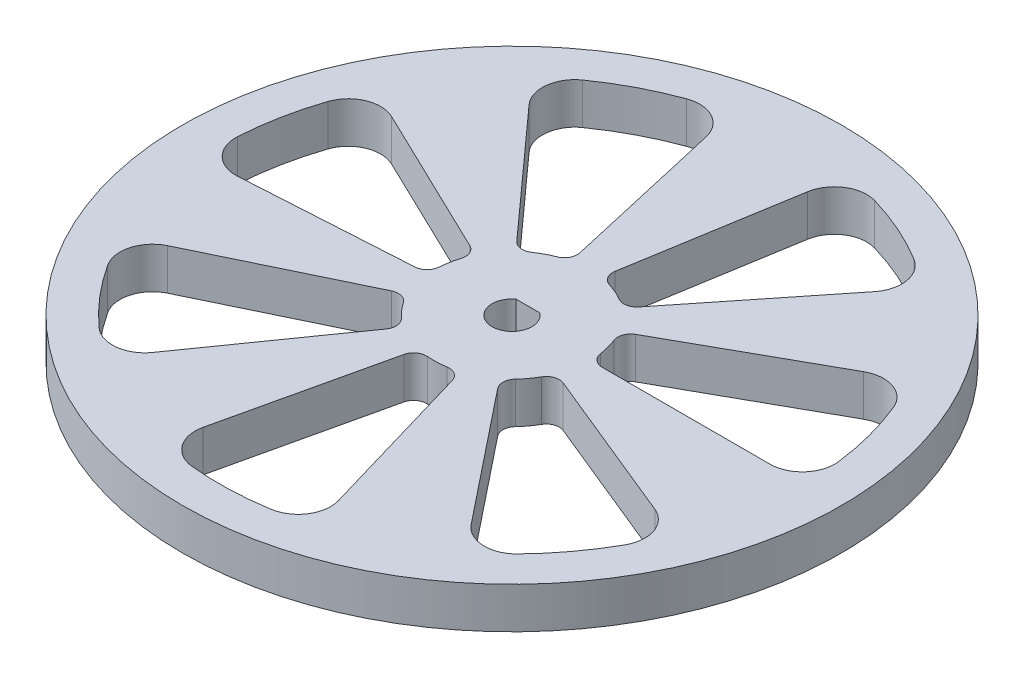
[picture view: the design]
ISO-10303-21;
HEADER;
FILE_DESCRIPTION(('STEP AP214'),'2;1');
FILE_NAME('part.step','',(''),(''),'','','');
FILE_SCHEMA(('AUTOMOTIVE_DESIGN { 1 0 10303 214 1 1 1 1 }'));
ENDSEC;
DATA;
#1=APPLICATION_CONTEXT('core data for automotive mechanical design processes');
#2=APPLICATION_PROTOCOL_DEFINITION('international standard','automotive_design',2000,#1);
#3=PRODUCT_CONTEXT('',#1,'mechanical');
#4=PRODUCT('Part','Part','',(#3));
#5=PRODUCT_RELATED_PRODUCT_CATEGORY('part','',(#4));
#6=PRODUCT_DEFINITION_FORMATION('','',#4);
#7=PRODUCT_DEFINITION_CONTEXT('part definition',#1,'design');
#8=PRODUCT_DEFINITION('design','',#6,#7);
#9=PRODUCT_DEFINITION_SHAPE('','',#8);
#10=(LENGTH_UNIT() NAMED_UNIT(*) SI_UNIT(.MILLI.,.METRE.));
#11=(NAMED_UNIT(*) PLANE_ANGLE_UNIT() SI_UNIT($,.RADIAN.));
#12=(NAMED_UNIT(*) SI_UNIT($,.STERADIAN.) SOLID_ANGLE_UNIT());
#13=UNCERTAINTY_MEASURE_WITH_UNIT(LENGTH_MEASURE(1.E-05),#10,'distance_accuracy_value','');
#14=(GEOMETRIC_REPRESENTATION_CONTEXT(3) GLOBAL_UNCERTAINTY_ASSIGNED_CONTEXT((#13)) GLOBAL_UNIT_ASSIGNED_CONTEXT((#10,
#11,#12)) REPRESENTATION_CONTEXT('',''));
#15=CARTESIAN_POINT('',(0.,0.,0.));
#16=DIRECTION('',(0.,0.,1.));
#17=DIRECTION('',(1.,0.,0.));
#18=AXIS2_PLACEMENT_3D('',#15,#16,#17);
#19=CARTESIAN_POINT('',(0.,6.35,0.));
#20=DIRECTION('',(0.,1.,0.));
#21=DIRECTION('',(0.,0.,1.));
#22=AXIS2_PLACEMENT_3D('',#19,#20,#21);
#23=PLANE('',#22);
#24=CARTESIAN_POINT('',(0.,6.35,0.));
#25=DIRECTION('',(0.,1.,0.));
#26=DIRECTION('',(0.,0.,1.));
#27=AXIS2_PLACEMENT_3D('',#24,#25,#26);
#28=CIRCLE('',#27,45.0699999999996);
#29=CARTESIAN_POINT('',(-15.4335390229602,6.35,-42.3451387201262));
#30=VERTEX_POINT('',#29);
#31=CARTESIAN_POINT('',(-25.9488114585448,6.35,-36.850564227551));
#32=VERTEX_POINT('',#31);
#33=EDGE_CURVE('E463',#30,#32,#28,.T.);
#34=ORIENTED_EDGE('',*,*,#33,.F.);
#35=CARTESIAN_POINT('',(-13.7213647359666,6.35,-37.6474308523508));
#36=DIRECTION('',(0.,1.,0.));
#37=DIRECTION('',(0.,0.,1.));
#38=AXIS2_PLACEMENT_3D('',#35,#36,#37);
#39=CIRCLE('',#38,5.);
#40=CARTESIAN_POINT('',(-8.84672517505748,6.35,-38.7600355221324));
#41=VERTEX_POINT('',#40);
#42=EDGE_CURVE('E461',#41,#30,#39,.T.);
#43=ORIENTED_EDGE('',*,*,#42,.F.);
#44=DIRECTION('',(-0.222520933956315,0.,-0.974927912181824));
#45=VECTOR('',#44,1.);
#46=CARTESIAN_POINT('',(-3.09907757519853,6.35,-13.5779460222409));
#47=LINE('',#46,#45);
#48=CARTESIAN_POINT('',(-3.09907757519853,6.35,-13.5779460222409));
#49=VERTEX_POINT('',#48);
#50=EDGE_CURVE('E477',#49,#41,#47,.T.);
#51=ORIENTED_EDGE('',*,*,#50,.F.);
#52=CARTESIAN_POINT('',(-5.04893339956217,6.35,-13.1329041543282));
#53=DIRECTION('',(0.,1.,0.));
#54=DIRECTION('',(0.,0.,1.));
#55=AXIS2_PLACEMENT_3D('',#52,#53,#54);
#56=CIRCLE('',#55,2.);
#57=CARTESIAN_POINT('',(-4.33124563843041,6.35,-11.2661089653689));
#58=VERTEX_POINT('',#57);
#59=EDGE_CURVE('E474',#58,#49,#56,.T.);
#60=ORIENTED_EDGE('',*,*,#59,.F.);
#61=CARTESIAN_POINT('',(0.,6.35,0.));
#62=DIRECTION('',(0.,-1.,0.));
#63=DIRECTION('',(0.,0.,1.));
#64=AXIS2_PLACEMENT_3D('',#61,#62,#63);
#65=CIRCLE('',#64,12.0699999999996);
#66=CARTESIAN_POINT('',(-6.86861851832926,6.35,-9.92506824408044));
#67=VERTEX_POINT('',#66);
#68=EDGE_CURVE('E472',#67,#58,#65,.T.);
#69=ORIENTED_EDGE('',*,*,#68,.F.);
#70=CARTESIAN_POINT('',(-8.00674917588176,6.35,-11.569652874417));
#71=DIRECTION('',(0.,1.,0.));
#72=DIRECTION('',(0.,0.,-1.));
#73=AXIS2_PLACEMENT_3D('',#70,#71,#72);
#74=CIRCLE('',#73,2.);
#75=CARTESIAN_POINT('',(-9.49233831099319,6.35,-10.2306140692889));
#76=VERTEX_POINT('',#75);
#77=EDGE_CURVE('E470',#76,#67,#74,.T.);
#78=ORIENTED_EDGE('',*,*,#77,.F.);
#79=DIRECTION('',(0.669519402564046,0.,0.742794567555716));
#80=VECTOR('',#79,1.);
#81=CARTESIAN_POINT('',(-9.49233831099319,6.35,-10.2306140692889));
#82=LINE('',#81,#80);
#83=CARTESIAN_POINT('',(-26.7840610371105,6.35,-29.4148194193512));
#84=VERTEX_POINT('',#83);
#85=EDGE_CURVE('E468',#84,#76,#82,.T.);
#86=ORIENTED_EDGE('',*,*,#85,.F.);
#87=CARTESIAN_POINT('',(-23.0700881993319,6.35,-32.7624164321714));
#88=DIRECTION('',(0.,1.,0.));
#89=DIRECTION('',(0.,0.,-1.));
#90=AXIS2_PLACEMENT_3D('',#87,#88,#89);
#91=CIRCLE('',#90,5.);
#92=EDGE_CURVE('E466',#32,#84,#91,.T.);
#93=ORIENTED_EDGE('',*,*,#92,.F.);
#94=EDGE_LOOP('',(#34,#43,#51,#60,#69,#78,#86,#93));
#95=FACE_BOUND('',#94,.T.);
#96=CARTESIAN_POINT('',(0.,6.35,0.));
#97=DIRECTION('',(0.,1.,0.));
#98=DIRECTION('',(0.,0.,1.));
#99=AXIS2_PLACEMENT_3D('',#96,#97,#98);
#100=CIRCLE('',#99,45.0700000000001);
#101=CARTESIAN_POINT('',(-37.8491721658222,6.35,24.469267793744));
#102=VERTEX_POINT('',#101);
#103=CARTESIAN_POINT('',(-30.152489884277,6.35,33.4982425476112));
#104=VERTEX_POINT('',#103);
#105=EDGE_CURVE('E581',#102,#104,#100,.T.);
#106=ORIENTED_EDGE('',*,*,#105,.F.);
#107=CARTESIAN_POINT('',(-33.6502402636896,6.35,21.7546829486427));
#108=DIRECTION('',(0.,1.,0.));
#109=DIRECTION('',(0.,0.,1.));
#110=AXIS2_PLACEMENT_3D('',#107,#108,#109);
#111=CIRCLE('',#110,5.);
#112=CARTESIAN_POINT('',(-35.8196589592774,6.35,17.2498386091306));
#113=VERTEX_POINT('',#112);
#114=EDGE_CURVE('E579',#113,#102,#111,.T.);
#115=ORIENTED_EDGE('',*,*,#114,.F.);
#116=DIRECTION('',(-0.900968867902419,0.,0.433883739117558));
#117=VECTOR('',#116,1.);
#118=CARTESIAN_POINT('',(-12.5479089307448,6.35,6.04275446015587));
#119=LINE('',#118,#117);
#120=CARTESIAN_POINT('',(-12.5479089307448,6.35,6.04275446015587));
#121=VERTEX_POINT('',#120);
#122=EDGE_CURVE('E595',#121,#113,#119,.T.);
#123=ORIENTED_EDGE('',*,*,#122,.F.);
#124=CARTESIAN_POINT('',(-11.6801414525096,6.35,7.84469219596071));
#125=DIRECTION('',(0.,1.,0.));
#126=DIRECTION('',(0.,0.,1.));
#127=AXIS2_PLACEMENT_3D('',#124,#125,#126);
#128=CIRCLE('',#127,2.);
#129=CARTESIAN_POINT('',(-10.0198512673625,6.35,6.72959735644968));
#130=VERTEX_POINT('',#129);
#131=EDGE_CURVE('E592',#130,#121,#128,.T.);
#132=ORIENTED_EDGE('',*,*,#131,.F.);
#133=CARTESIAN_POINT('',(0.,6.35,0.));
#134=DIRECTION('',(0.,-1.,0.));
#135=DIRECTION('',(0.,0.,1.));
#136=AXIS2_PLACEMENT_3D('',#133,#134,#135);
#137=CIRCLE('',#136,12.0700000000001);
#138=CARTESIAN_POINT('',(-8.14781465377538,6.35,8.90494336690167));
#139=VERTEX_POINT('',#138);
#140=EDGE_CURVE('E590',#139,#130,#137,.T.);
#141=ORIENTED_EDGE('',*,*,#140,.F.);
#142=CARTESIAN_POINT('',(-9.49790821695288,6.35,10.3804932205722));
#143=DIRECTION('',(0.,1.,0.));
#144=DIRECTION('',(0.,0.,-1.));
#145=AXIS2_PLACEMENT_3D('',#142,#143,#144);
#146=CIRCLE('',#145,2.);
#147=CARTESIAN_POINT('',(-7.86186722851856,6.35,11.5308713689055));
#148=VERTEX_POINT('',#147);
#149=EDGE_CURVE('E588',#148,#139,#146,.T.);
#150=ORIENTED_EDGE('',*,*,#149,.F.);
#151=DIRECTION('',(0.57518907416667,0.,-0.818020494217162));
#152=VECTOR('',#151,1.);
#153=CARTESIAN_POINT('',(-7.86186722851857,6.35,11.5308713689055));
#154=LINE('',#153,#152);
#155=CARTESIAN_POINT('',(-22.7173142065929,6.35,32.6579417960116));
#156=VERTEX_POINT('',#155);
#157=EDGE_CURVE('E586',#156,#148,#154,.T.);
#158=ORIENTED_EDGE('',*,*,#157,.F.);
#159=CARTESIAN_POINT('',(-26.8074166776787,6.35,29.7819964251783));
#160=DIRECTION('',(0.,1.,0.));
#161=DIRECTION('',(0.,0.,-1.));
#162=AXIS2_PLACEMENT_3D('',#159,#160,#161);
#163=CIRCLE('',#162,5.);
#164=EDGE_CURVE('E584',#104,#156,#163,.T.);
#165=ORIENTED_EDGE('',*,*,#164,.F.);
#166=EDGE_LOOP('',(#106,#115,#123,#132,#141,#150,#158,#165));
#167=FACE_BOUND('',#166,.T.);
#168=CARTESIAN_POINT('',(0.,6.35,0.));
#169=DIRECTION('',(0.,1.,0.));
#170=DIRECTION('',(0.,0.,1.));
#171=AXIS2_PLACEMENT_3D('',#168,#169,#170);
#172=CIRCLE('',#171,45.0700000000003);
#173=CARTESIAN_POINT('',(32.2780053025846,6.35,31.4552900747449));
#174=VERTEX_POINT('',#173);
#175=CARTESIAN_POINT('',(39.3679318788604,6.35,21.9424437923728));
#176=VERTEX_POINT('',#175);
#177=EDGE_CURVE('E699',#174,#176,#172,.T.);
#178=ORIENTED_EDGE('',*,*,#177,.F.);
#179=CARTESIAN_POINT('',(28.6971305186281,6.35,27.9656861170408));
#180=DIRECTION('',(0.,1.,0.));
#181=DIRECTION('',(0.,0.,1.));
#182=AXIS2_PLACEMENT_3D('',#179,#180,#181);
#183=CIRCLE('',#182,5.);
#184=CARTESIAN_POINT('',(24.7879731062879,6.35,31.0831351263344));
#185=VERTEX_POINT('',#184);
#186=EDGE_CURVE('E697',#185,#174,#183,.T.);
#187=ORIENTED_EDGE('',*,*,#186,.F.);
#188=DIRECTION('',(0.623489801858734,0.,0.78183148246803));
#189=VECTOR('',#188,1.);
#190=CARTESIAN_POINT('',(8.68342240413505,6.35,10.8886672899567));
#191=LINE('',#190,#189);
#192=CARTESIAN_POINT('',(8.68342240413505,6.35,10.8886672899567));
#193=VERTEX_POINT('',#192);
#194=EDGE_CURVE('E713',#193,#185,#191,.T.);
#195=ORIENTED_EDGE('',*,*,#194,.F.);
#196=CARTESIAN_POINT('',(10.2470853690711,6.35,9.6416876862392));
#197=DIRECTION('',(0.,1.,0.));
#198=DIRECTION('',(0.,0.,1.));
#199=AXIS2_PLACEMENT_3D('',#196,#197,#198);
#200=CIRCLE('',#199,2.);
#201=CARTESIAN_POINT('',(8.79049896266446,6.35,8.2711563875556));
#202=VERTEX_POINT('',#201);
#203=EDGE_CURVE('E710',#202,#193,#200,.T.);
#204=ORIENTED_EDGE('',*,*,#203,.F.);
#205=CARTESIAN_POINT('',(0.,6.35,0.));
#206=DIRECTION('',(0.,-1.,0.));
#207=DIRECTION('',(0.,0.,1.));
#208=AXIS2_PLACEMENT_3D('',#205,#206,#207);
#209=CIRCLE('',#208,12.0700000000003);
#210=CARTESIAN_POINT('',(10.4947371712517,6.35,5.96199561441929));
#211=VERTEX_POINT('',#210);
#212=EDGE_CURVE('E708',#211,#202,#209,.T.);
#213=ORIENTED_EDGE('',*,*,#212,.F.);
#214=CARTESIAN_POINT('',(12.2337159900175,6.35,6.94989878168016));
#215=DIRECTION('',(0.,1.,0.));
#216=DIRECTION('',(0.,0.,-1.));
#217=AXIS2_PLACEMENT_3D('',#214,#215,#216);
#218=CIRCLE('',#217,2.);
#219=CARTESIAN_POINT('',(12.9911983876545,6.35,5.09889353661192));
#220=VERTEX_POINT('',#219);
#221=EDGE_CURVE('E706',#220,#211,#218,.T.);
#222=ORIENTED_EDGE('',*,*,#221,.F.);
#223=DIRECTION('',(-0.925502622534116,0.,-0.378741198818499));
#224=VECTOR('',#223,1.);
#225=CARTESIAN_POINT('',(12.9911983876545,6.35,5.09889353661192));
#226=LINE('',#225,#224);
#227=CARTESIAN_POINT('',(36.894216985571,6.35,14.8806680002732));
#228=VERTEX_POINT('',#227);
#229=EDGE_CURVE('E704',#228,#220,#226,.T.);
#230=ORIENTED_EDGE('',*,*,#229,.F.);
#231=CARTESIAN_POINT('',(35.0005109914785,6.35,19.5081811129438));
#232=DIRECTION('',(0.,1.,0.));
#233=DIRECTION('',(0.,0.,-1.));
#234=AXIS2_PLACEMENT_3D('',#231,#232,#233);
#235=CIRCLE('',#234,5.);
#236=EDGE_CURVE('E702',#176,#228,#235,.T.);
#237=ORIENTED_EDGE('',*,*,#236,.F.);
#238=EDGE_LOOP('',(#178,#187,#195,#204,#213,#222,#230,#237));
#239=FACE_BOUND('',#238,.T.);
#240=CARTESIAN_POINT('',(0.,6.35,0.));
#241=DIRECTION('',(0.,1.,0.));
#242=DIRECTION('',(0.,0.,1.));
#243=AXIS2_PLACEMENT_3D('',#240,#241,#242);
#244=CIRCLE('',#243,45.07);
#245=CARTESIAN_POINT('',(44.7177432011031,6.35,-5.62390816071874));
#246=VERTEX_POINT('',#245);
#247=CARTESIAN_POINT('',(41.7007974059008,6.35,-17.0981986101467));
#248=VERTEX_POINT('',#247);
#249=EDGE_CURVE('E775',#246,#248,#244,.T.);
#250=ORIENTED_EDGE('',*,*,#249,.F.);
#251=CARTESIAN_POINT('',(39.756822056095,6.35,-5.));
#252=DIRECTION('',(0.,1.,0.));
#253=DIRECTION('',(0.,0.,1.));
#254=AXIS2_PLACEMENT_3D('',#251,#252,#253);
#255=CIRCLE('',#254,5.);
#256=CARTESIAN_POINT('',(39.756822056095,6.35,0.));
#257=VERTEX_POINT('',#256);
#258=EDGE_CURVE('E773',#257,#246,#255,.T.);
#259=ORIENTED_EDGE('',*,*,#258,.F.);
#260=DIRECTION('',(1.,0.,0.));
#261=VECTOR('',#260,1.);
#262=CARTESIAN_POINT('',(13.9271282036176,6.35,0.));
#263=LINE('',#262,#261);
#264=CARTESIAN_POINT('',(13.9271282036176,6.35,0.));
#265=VERTEX_POINT('',#264);
#266=EDGE_CURVE('E789',#265,#257,#263,.T.);
#267=ORIENTED_EDGE('',*,*,#266,.F.);
#268=CARTESIAN_POINT('',(13.9271282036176,6.35,-2.));
#269=DIRECTION('',(0.,1.,0.));
#270=DIRECTION('',(0.,0.,1.));
#271=AXIS2_PLACEMENT_3D('',#268,#269,#270);
#272=CIRCLE('',#271,2.);
#273=CARTESIAN_POINT('',(11.9474369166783,6.35,-1.71570717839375));
#274=VERTEX_POINT('',#273);
#275=EDGE_CURVE('E786',#274,#265,#272,.T.);
#276=ORIENTED_EDGE('',*,*,#275,.F.);
#277=CARTESIAN_POINT('',(0.,6.35,0.));
#278=DIRECTION('',(0.,-1.,0.));
#279=DIRECTION('',(0.,0.,1.));
#280=AXIS2_PLACEMENT_3D('',#277,#278,#279);
#281=CIRCLE('',#280,12.07);
#282=CARTESIAN_POINT('',(11.2046374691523,6.35,-4.4878724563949));
#283=VERTEX_POINT('',#282);
#284=EDGE_CURVE('E784',#283,#274,#281,.T.);
#285=ORIENTED_EDGE('',*,*,#284,.F.);
#286=CARTESIAN_POINT('',(13.0612468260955,6.35,-5.23151329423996));
#287=DIRECTION('',(0.,1.,0.));
#288=DIRECTION('',(0.,0.,-1.));
#289=AXIS2_PLACEMENT_3D('',#286,#287,#288);
#290=CIRCLE('',#289,2.);
#291=CARTESIAN_POINT('',(12.0863552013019,6.35,-6.977819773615));
#292=VERTEX_POINT('',#291);
#293=EDGE_CURVE('E782',#292,#283,#290,.T.);
#294=ORIENTED_EDGE('',*,*,#293,.F.);
#295=DIRECTION('',(-0.87315323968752,0.,0.487445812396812));
#296=VECTOR('',#295,1.);
#297=CARTESIAN_POINT('',(12.0863552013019,6.35,-6.977819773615));
#298=LINE('',#297,#296);
#299=CARTESIAN_POINT('',(34.6373427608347,6.35,-19.56711561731));
#300=VERTEX_POINT('',#299);
#301=EDGE_CURVE('E780',#300,#292,#298,.T.);
#302=ORIENTED_EDGE('',*,*,#301,.F.);
#303=CARTESIAN_POINT('',(37.0745718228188,6.35,-15.2013494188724));
#304=DIRECTION('',(0.,1.,0.));
#305=DIRECTION('',(0.,0.,-1.));
#306=AXIS2_PLACEMENT_3D('',#303,#304,#305);
#307=CIRCLE('',#306,5.);
#308=EDGE_CURVE('E778',#248,#300,#307,.T.);
#309=ORIENTED_EDGE('',*,*,#308,.F.);
#310=EDGE_LOOP('',(#250,#259,#267,#276,#285,#294,#302,#309));
#311=FACE_BOUND('',#310,.T.);
#312=CARTESIAN_POINT('',(0.,6.35,0.));
#313=DIRECTION('',(0.,1.,0.));
#314=DIRECTION('',(0.,0.,1.));
#315=AXIS2_PLACEMENT_3D('',#312,#313,#314);
#316=CIRCLE('',#315,50.8);
#317=CARTESIAN_POINT('',(0.,6.35,50.8));
#318=VERTEX_POINT('',#317);
#319=EDGE_CURVE('E11',#318,#318,#316,.T.);
#320=ORIENTED_EDGE('',*,*,#319,.T.);
#321=EDGE_LOOP('',(#320));
#322=FACE_BOUND('',#321,.T.);
#323=DIRECTION('',(-1.,0.,0.));
#324=VECTOR('',#323,1.);
#325=CARTESIAN_POINT('',(1.83187666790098,6.35,-2.46356));
#326=LINE('',#325,#324);
#327=CARTESIAN_POINT('',(1.83187666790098,6.35,-2.46356));
#328=VERTEX_POINT('',#327);
#329=CARTESIAN_POINT('',(-1.83187666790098,6.35,-2.46356));
#330=VERTEX_POINT('',#329);
#331=EDGE_CURVE('E759',#328,#330,#326,.T.);
#332=ORIENTED_EDGE('',*,*,#331,.F.);
#333=CARTESIAN_POINT('',(0.,6.35,0.));
#334=DIRECTION('',(0.,1.,0.));
#335=DIRECTION('',(0.,0.,1.));
#336=AXIS2_PLACEMENT_3D('',#333,#334,#335);
#337=CIRCLE('',#336,3.07);
#338=EDGE_CURVE('E756',#330,#328,#337,.T.);
#339=ORIENTED_EDGE('',*,*,#338,.F.);
#340=EDGE_LOOP('',(#332,#339));
#341=FACE_BOUND('',#340,.T.);
#342=CARTESIAN_POINT('',(0.,6.35,0.));
#343=DIRECTION('',(0.,1.,0.));
#344=DIRECTION('',(0.,0.,1.));
#345=AXIS2_PLACEMENT_3D('',#342,#343,#344);
#346=CIRCLE('',#345,45.0700000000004);
#347=CARTESIAN_POINT('',(-4.46772894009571,6.35,44.8480133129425));
#348=VERTEX_POINT('',#347);
#349=CARTESIAN_POINT('',(7.39021068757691,6.35,44.4599784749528));
#350=VERTEX_POINT('',#349);
#351=EDGE_CURVE('E640',#348,#350,#346,.T.);
#352=ORIENTED_EDGE('',*,*,#351,.F.);
#353=CARTESIAN_POINT('',(-3.9720856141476,6.35,39.8726401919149));
#354=DIRECTION('',(0.,1.,0.));
#355=DIRECTION('',(0.,0.,1.));
#356=AXIS2_PLACEMENT_3D('',#353,#354,#355);
#357=CIRCLE('',#356,5.);
#358=CARTESIAN_POINT('',(-8.84672517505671,6.35,38.7600355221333));
#359=VERTEX_POINT('',#358);
#360=EDGE_CURVE('E638',#359,#348,#357,.T.);
#361=ORIENTED_EDGE('',*,*,#360,.F.);
#362=DIRECTION('',(-0.222520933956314,0.,0.974927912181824));
#363=VECTOR('',#362,1.);
#364=CARTESIAN_POINT('',(-3.09907757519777,6.35,13.5779460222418));
#365=LINE('',#364,#363);
#366=CARTESIAN_POINT('',(-3.09907757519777,6.35,13.5779460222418));
#367=VERTEX_POINT('',#366);
#368=EDGE_CURVE('E654',#367,#359,#365,.T.);
#369=ORIENTED_EDGE('',*,*,#368,.F.);
#370=CARTESIAN_POINT('',(-1.14922175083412,6.35,14.0229878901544));
#371=DIRECTION('',(0.,1.,0.));
#372=DIRECTION('',(0.,0.,1.));
#373=AXIS2_PLACEMENT_3D('',#370,#371,#372);
#374=CIRCLE('',#373,2.);
#375=CARTESIAN_POINT('',(-0.98586400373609,6.35,12.0296704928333));
#376=VERTEX_POINT('',#375);
#377=EDGE_CURVE('E651',#376,#367,#374,.T.);
#378=ORIENTED_EDGE('',*,*,#377,.F.);
#379=CARTESIAN_POINT('',(0.,6.35,0.));
#380=DIRECTION('',(0.,-1.,0.));
#381=DIRECTION('',(0.,0.,1.));
#382=AXIS2_PLACEMENT_3D('',#379,#380,#381);
#383=CIRCLE('',#382,12.0700000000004);
#384=CARTESIAN_POINT('',(1.88208572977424,6.35,11.922359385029));
#385=VERTEX_POINT('',#384);
#386=EDGE_CURVE('E649',#385,#376,#383,.T.);
#387=ORIENTED_EDGE('',*,*,#386,.F.);
#388=CARTESIAN_POINT('',(2.19394749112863,6.35,13.8978953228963));
#389=DIRECTION('',(0.,1.,0.));
#390=DIRECTION('',(0.,0.,-1.));
#391=AXIS2_PLACEMENT_3D('',#388,#389,#390);
#392=CIRCLE('',#391,2.);
#393=CARTESIAN_POINT('',(4.1134042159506,6.35,13.3360360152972));
#394=VERTEX_POINT('',#393);
#395=EDGE_CURVE('E647',#394,#385,#392,.T.);
#396=ORIENTED_EDGE('',*,*,#395,.F.);
#397=DIRECTION('',(-0.280929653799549,0.,-0.959728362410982));
#398=VECTOR('',#397,1.);
#399=CARTESIAN_POINT('',(4.11340421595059,6.35,13.3360360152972));
#400=LINE('',#399,#398);
#401=CARTESIAN_POINT('',(11.368993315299,6.35,38.1230051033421));
#402=VERTEX_POINT('',#401);
#403=EDGE_CURVE('E645',#402,#394,#400,.T.);
#404=ORIENTED_EDGE('',*,*,#403,.F.);
#405=CARTESIAN_POINT('',(6.57035150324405,6.35,39.5276533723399));
#406=DIRECTION('',(0.,1.,0.));
#407=DIRECTION('',(0.,0.,-1.));
#408=AXIS2_PLACEMENT_3D('',#405,#406,#407);
#409=CIRCLE('',#408,5.);
#410=EDGE_CURVE('E643',#350,#402,#409,.T.);
#411=ORIENTED_EDGE('',*,*,#410,.F.);
#412=EDGE_LOOP('',(#352,#361,#369,#378,#387,#396,#404,#411));
#413=FACE_BOUND('',#412,.T.);
#414=CARTESIAN_POINT('',(0.,6.35,0.));
#415=DIRECTION('',(0.,1.,0.));
#416=DIRECTION('',(0.,0.,1.));
#417=AXIS2_PLACEMENT_3D('',#414,#415,#416);
#418=CIRCLE('',#417,45.0699999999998);
#419=CARTESIAN_POINT('',(-42.7294167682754,6.35,-14.3353354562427));
#420=VERTEX_POINT('',#419);
#421=CARTESIAN_POINT('',(-44.9897505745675,6.35,-2.68835325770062));
#422=VERTEX_POINT('',#421);
#423=EDGE_CURVE('E522',#420,#422,#418,.T.);
#424=ORIENTED_EDGE('',*,*,#423,.F.);
#425=CARTESIAN_POINT('',(-37.9890776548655,6.35,-12.744994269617));
#426=DIRECTION('',(0.,1.,0.));
#427=DIRECTION('',(0.,0.,1.));
#428=AXIS2_PLACEMENT_3D('',#425,#426,#427);
#429=CIRCLE('',#428,5.);
#430=CARTESIAN_POINT('',(-35.8196589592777,6.35,-17.2498386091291));
#431=VERTEX_POINT('',#430);
#432=EDGE_CURVE('E520',#431,#420,#429,.T.);
#433=ORIENTED_EDGE('',*,*,#432,.F.);
#434=DIRECTION('',(-0.900968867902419,0.,-0.433883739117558));
#435=VECTOR('',#434,1.);
#436=CARTESIAN_POINT('',(-12.5479089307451,6.35,-6.0427544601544));
#437=LINE('',#436,#435);
#438=CARTESIAN_POINT('',(-12.5479089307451,6.35,-6.0427544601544));
#439=VERTEX_POINT('',#438);
#440=EDGE_CURVE('E536',#439,#431,#437,.T.);
#441=ORIENTED_EDGE('',*,*,#440,.F.);
#442=CARTESIAN_POINT('',(-13.4156764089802,6.35,-4.24081672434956));
#443=DIRECTION('',(0.,1.,0.));
#444=DIRECTION('',(0.,0.,1.));
#445=AXIS2_PLACEMENT_3D('',#442,#443,#444);
#446=CIRCLE('',#445,2.);
#447=CARTESIAN_POINT('',(-11.5086861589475,6.35,-3.63799984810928));
#448=VERTEX_POINT('',#447);
#449=EDGE_CURVE('E533',#448,#439,#446,.T.);
#450=ORIENTED_EDGE('',*,*,#449,.F.);
#451=CARTESIAN_POINT('',(0.,6.35,0.));
#452=DIRECTION('',(0.,-1.,0.));
#453=DIRECTION('',(0.,0.,1.));
#454=AXIS2_PLACEMENT_3D('',#451,#452,#453);
#455=CIRCLE('',#454,12.0699999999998);
#456=CARTESIAN_POINT('',(-12.0422444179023,6.35,-0.818076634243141));
#457=VERTEX_POINT('',#456);
#458=EDGE_CURVE('E531',#457,#448,#455,.T.);
#459=ORIENTED_EDGE('',*,*,#458,.F.);
#460=CARTESIAN_POINT('',(-14.0376453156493,6.35,-0.953632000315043));
#461=DIRECTION('',(0.,1.,0.));
#462=DIRECTION('',(0.,0.,-1.));
#463=AXIS2_PLACEMENT_3D('',#460,#461,#462);
#464=CIRCLE('',#463,2.);
#465=CARTESIAN_POINT('',(-13.9169922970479,6.35,1.042725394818));
#466=VERTEX_POINT('',#465);
#467=EDGE_CURVE('E529',#466,#457,#464,.T.);
#468=ORIENTED_EDGE('',*,*,#467,.F.);
#469=DIRECTION('',(0.998178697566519,0.,-0.0603265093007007));
#470=VECTOR('',#469,1.);
#471=CARTESIAN_POINT('',(-13.9169922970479,6.35,1.04272539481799));
#472=LINE('',#471,#470);
#473=CARTESIAN_POINT('',(-39.6970207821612,6.35,2.60078221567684));
#474=VERTEX_POINT('',#473);
#475=EDGE_CURVE('E527',#474,#466,#472,.T.);
#476=ORIENTED_EDGE('',*,*,#475,.F.);
#477=CARTESIAN_POINT('',(-39.9986533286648,6.35,-2.39011127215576));
#478=DIRECTION('',(0.,1.,0.));
#479=DIRECTION('',(0.,0.,-1.));
#480=AXIS2_PLACEMENT_3D('',#477,#478,#479);
#481=CIRCLE('',#480,5.);
#482=EDGE_CURVE('E525',#422,#474,#481,.T.);
#483=ORIENTED_EDGE('',*,*,#482,.F.);
#484=EDGE_LOOP('',(#424,#433,#441,#450,#459,#468,#476,#483));
#485=FACE_BOUND('',#484,.T.);
#486=CARTESIAN_POINT('',(0.,6.35,0.));
#487=DIRECTION('',(0.,1.,0.));
#488=DIRECTION('',(0.,0.,1.));
#489=AXIS2_PLACEMENT_3D('',#486,#487,#488);
#490=CIRCLE('',#489,45.0699999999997);
#491=CARTESIAN_POINT('',(23.4841083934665,6.35,-38.4681888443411));
#492=VERTEX_POINT('',#491);
#493=CARTESIAN_POINT('',(12.6321119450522,6.35,-43.2635487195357));
#494=VERTEX_POINT('',#493);
#495=EDGE_CURVE('E404',#492,#494,#490,.T.);
#496=ORIENTED_EDGE('',*,*,#495,.F.);
#497=CARTESIAN_POINT('',(20.8788156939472,6.35,-34.2005841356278));
#498=DIRECTION('',(0.,1.,0.));
#499=DIRECTION('',(0.,0.,1.));
#500=AXIS2_PLACEMENT_3D('',#497,#498,#499);
#501=CIRCLE('',#500,5.);
#502=CARTESIAN_POINT('',(24.7879731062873,6.35,-31.0831351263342));
#503=VERTEX_POINT('',#502);
#504=EDGE_CURVE('E396',#503,#492,#501,.T.);
#505=ORIENTED_EDGE('',*,*,#504,.F.);
#506=DIRECTION('',(0.623489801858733,0.,-0.78183148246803));
#507=VECTOR('',#506,1.);
#508=CARTESIAN_POINT('',(8.68342240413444,6.35,-10.8886672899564));
#509=LINE('',#508,#507);
#510=CARTESIAN_POINT('',(8.68342240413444,6.35,-10.8886672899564));
#511=VERTEX_POINT('',#510);
#512=EDGE_CURVE('E429',#511,#503,#509,.T.);
#513=ORIENTED_EDGE('',*,*,#512,.F.);
#514=CARTESIAN_POINT('',(7.11975943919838,6.35,-12.1356468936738));
#515=DIRECTION('',(0.,1.,0.));
#516=DIRECTION('',(0.,0.,1.));
#517=AXIS2_PLACEMENT_3D('',#514,#515,#516);
#518=CIRCLE('',#517,2.);
#519=CARTESIAN_POINT('',(6.10771118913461,6.35,-10.410608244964));
#520=VERTEX_POINT('',#519);
#521=EDGE_CURVE('E427',#520,#511,#518,.T.);
#522=ORIENTED_EDGE('',*,*,#521,.F.);
#523=CARTESIAN_POINT('',(0.,6.35,0.));
#524=DIRECTION('',(0.,-1.,0.));
#525=DIRECTION('',(0.,0.,1.));
#526=AXIS2_PLACEMENT_3D('',#523,#524,#525);
#527=CIRCLE('',#526,12.0699999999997);
#528=CARTESIAN_POINT('',(3.47721721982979,6.35,-11.5582810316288));
#529=VERTEX_POINT('',#528);
#530=EDGE_CURVE('E425',#529,#520,#527,.T.);
#531=ORIENTED_EDGE('',*,*,#530,.F.);
#532=CARTESIAN_POINT('',(4.05339240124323,6.35,-13.4734891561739));
#533=DIRECTION('',(0.,1.,0.));
#534=DIRECTION('',(0.,0.,-1.));
#535=AXIS2_PLACEMENT_3D('',#532,#533,#534);
#536=CIRCLE('',#535,2.);
#537=CARTESIAN_POINT('',(2.0802400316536,6.35,-13.800092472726));
#538=VERTEX_POINT('',#537);
#539=EDGE_CURVE('E423',#538,#529,#536,.T.);
#540=ORIENTED_EDGE('',*,*,#539,.F.);
#541=DIRECTION('',(-0.16330165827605,0.,0.986576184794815));
#542=VECTOR('',#541,1.);
#543=CARTESIAN_POINT('',(2.0802400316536,6.35,-13.800092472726));
#544=LINE('',#543,#542);
#545=CARTESIAN_POINT('',(6.29784296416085,6.35,-39.28046207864));
#546=VERTEX_POINT('',#545);
#547=EDGE_CURVE('E419',#546,#538,#544,.T.);
#548=ORIENTED_EDGE('',*,*,#547,.F.);
#549=CARTESIAN_POINT('',(11.2307238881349,6.35,-38.4639537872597));
#550=DIRECTION('',(0.,1.,0.));
#551=DIRECTION('',(0.,0.,-1.));
#552=AXIS2_PLACEMENT_3D('',#549,#550,#551);
#553=CIRCLE('',#552,5.);
#554=EDGE_CURVE('E417',#494,#546,#553,.T.);
#555=ORIENTED_EDGE('',*,*,#554,.F.);
#556=EDGE_LOOP('',(#496,#505,#513,#522,#531,#540,#548,#555));
#557=FACE_BOUND('',#556,.T.);
#558=ADVANCED_FACE('F31',(#95,#167,#239,#311,#322,#341,#413,#485,#557),#23,.T.);
#559=CARTESIAN_POINT('',(0.,0.,0.));
#560=DIRECTION('',(0.,1.,0.));
#561=DIRECTION('',(0.,0.,1.));
#562=AXIS2_PLACEMENT_3D('',#559,#560,#561);
#563=PLANE('',#562);
#564=CARTESIAN_POINT('',(-13.7213647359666,0.,-37.6474308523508));
#565=DIRECTION('',(0.,1.,0.));
#566=DIRECTION('',(0.,0.,1.));
#567=AXIS2_PLACEMENT_3D('',#564,#565,#566);
#568=CIRCLE('',#567,5.);
#569=CARTESIAN_POINT('',(-8.84672517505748,0.,-38.7600355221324));
#570=VERTEX_POINT('',#569);
#571=CARTESIAN_POINT('',(-15.4335390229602,0.,-42.3451387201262));
#572=VERTEX_POINT('',#571);
#573=EDGE_CURVE('E412',#570,#572,#568,.T.);
#574=ORIENTED_EDGE('',*,*,#573,.T.);
#575=CARTESIAN_POINT('',(0.,0.,0.));
#576=DIRECTION('',(0.,1.,0.));
#577=DIRECTION('',(0.,0.,1.));
#578=AXIS2_PLACEMENT_3D('',#575,#576,#577);
#579=CIRCLE('',#578,45.0699999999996);
#580=CARTESIAN_POINT('',(-25.9488114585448,0.,-36.850564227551));
#581=VERTEX_POINT('',#580);
#582=EDGE_CURVE('E482',#572,#581,#579,.T.);
#583=ORIENTED_EDGE('',*,*,#582,.T.);
#584=CARTESIAN_POINT('',(-23.0700881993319,0.,-32.7624164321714));
#585=DIRECTION('',(0.,1.,0.));
#586=DIRECTION('',(0.,0.,-1.));
#587=AXIS2_PLACEMENT_3D('',#584,#585,#586);
#588=CIRCLE('',#587,5.);
#589=CARTESIAN_POINT('',(-26.7840610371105,0.,-29.4148194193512));
#590=VERTEX_POINT('',#589);
#591=EDGE_CURVE('E485',#581,#590,#588,.T.);
#592=ORIENTED_EDGE('',*,*,#591,.T.);
#593=DIRECTION('',(0.669519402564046,0.,0.742794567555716));
#594=VECTOR('',#593,1.);
#595=CARTESIAN_POINT('',(-9.49233831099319,0.,-10.2306140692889));
#596=LINE('',#595,#594);
#597=CARTESIAN_POINT('',(-9.49233831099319,0.,-10.2306140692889));
#598=VERTEX_POINT('',#597);
#599=EDGE_CURVE('E488',#590,#598,#596,.T.);
#600=ORIENTED_EDGE('',*,*,#599,.T.);
#601=CARTESIAN_POINT('',(-8.00674917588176,0.,-11.569652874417));
#602=DIRECTION('',(0.,1.,0.));
#603=DIRECTION('',(0.,0.,-1.));
#604=AXIS2_PLACEMENT_3D('',#601,#602,#603);
#605=CIRCLE('',#604,2.);
#606=CARTESIAN_POINT('',(-6.86861851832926,0.,-9.92506824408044));
#607=VERTEX_POINT('',#606);
#608=EDGE_CURVE('E491',#598,#607,#605,.T.);
#609=ORIENTED_EDGE('',*,*,#608,.T.);
#610=CARTESIAN_POINT('',(0.,0.,0.));
#611=DIRECTION('',(0.,-1.,0.));
#612=DIRECTION('',(0.,0.,1.));
#613=AXIS2_PLACEMENT_3D('',#610,#611,#612);
#614=CIRCLE('',#613,12.0699999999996);
#615=CARTESIAN_POINT('',(-4.33124563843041,0.,-11.2661089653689));
#616=VERTEX_POINT('',#615);
#617=EDGE_CURVE('E494',#607,#616,#614,.T.);
#618=ORIENTED_EDGE('',*,*,#617,.T.);
#619=CARTESIAN_POINT('',(-5.04893339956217,0.,-13.1329041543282));
#620=DIRECTION('',(0.,1.,0.));
#621=DIRECTION('',(0.,0.,1.));
#622=AXIS2_PLACEMENT_3D('',#619,#620,#621);
#623=CIRCLE('',#622,2.);
#624=CARTESIAN_POINT('',(-3.09907757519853,0.,-13.5779460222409));
#625=VERTEX_POINT('',#624);
#626=EDGE_CURVE('E497',#616,#625,#623,.T.);
#627=ORIENTED_EDGE('',*,*,#626,.T.);
#628=DIRECTION('',(-0.222520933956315,0.,-0.974927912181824));
#629=VECTOR('',#628,1.);
#630=CARTESIAN_POINT('',(-3.09907757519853,0.,-13.5779460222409));
#631=LINE('',#630,#629);
#632=EDGE_CURVE('E464',#625,#570,#631,.T.);
#633=ORIENTED_EDGE('',*,*,#632,.T.);
#634=EDGE_LOOP('',(#574,#583,#592,#600,#609,#618,#627,#633));
#635=FACE_BOUND('',#634,.T.);
#636=CARTESIAN_POINT('',(-33.6502402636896,0.,21.7546829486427));
#637=DIRECTION('',(0.,1.,0.));
#638=DIRECTION('',(0.,0.,1.));
#639=AXIS2_PLACEMENT_3D('',#636,#637,#638);
#640=CIRCLE('',#639,5.);
#641=CARTESIAN_POINT('',(-35.8196589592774,0.,17.2498386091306));
#642=VERTEX_POINT('',#641);
#643=CARTESIAN_POINT('',(-37.8491721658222,0.,24.469267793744));
#644=VERTEX_POINT('',#643);
#645=EDGE_CURVE('E578',#642,#644,#640,.T.);
#646=ORIENTED_EDGE('',*,*,#645,.T.);
#647=CARTESIAN_POINT('',(0.,0.,0.));
#648=DIRECTION('',(0.,1.,0.));
#649=DIRECTION('',(0.,0.,1.));
#650=AXIS2_PLACEMENT_3D('',#647,#648,#649);
#651=CIRCLE('',#650,45.0700000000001);
#652=CARTESIAN_POINT('',(-30.152489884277,0.,33.4982425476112));
#653=VERTEX_POINT('',#652);
#654=EDGE_CURVE('E600',#644,#653,#651,.T.);
#655=ORIENTED_EDGE('',*,*,#654,.T.);
#656=CARTESIAN_POINT('',(-26.8074166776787,0.,29.7819964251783));
#657=DIRECTION('',(0.,1.,0.));
#658=DIRECTION('',(0.,0.,-1.));
#659=AXIS2_PLACEMENT_3D('',#656,#657,#658);
#660=CIRCLE('',#659,5.);
#661=CARTESIAN_POINT('',(-22.7173142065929,0.,32.6579417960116));
#662=VERTEX_POINT('',#661);
#663=EDGE_CURVE('E603',#653,#662,#660,.T.);
#664=ORIENTED_EDGE('',*,*,#663,.T.);
#665=DIRECTION('',(0.57518907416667,0.,-0.818020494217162));
#666=VECTOR('',#665,1.);
#667=CARTESIAN_POINT('',(-7.86186722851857,0.,11.5308713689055));
#668=LINE('',#667,#666);
#669=CARTESIAN_POINT('',(-7.86186722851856,0.,11.5308713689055));
#670=VERTEX_POINT('',#669);
#671=EDGE_CURVE('E606',#662,#670,#668,.T.);
#672=ORIENTED_EDGE('',*,*,#671,.T.);
#673=CARTESIAN_POINT('',(-9.49790821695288,0.,10.3804932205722));
#674=DIRECTION('',(0.,1.,0.));
#675=DIRECTION('',(0.,0.,-1.));
#676=AXIS2_PLACEMENT_3D('',#673,#674,#675);
#677=CIRCLE('',#676,2.);
#678=CARTESIAN_POINT('',(-8.14781465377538,0.,8.90494336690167));
#679=VERTEX_POINT('',#678);
#680=EDGE_CURVE('E609',#670,#679,#677,.T.);
#681=ORIENTED_EDGE('',*,*,#680,.T.);
#682=CARTESIAN_POINT('',(0.,0.,0.));
#683=DIRECTION('',(0.,-1.,0.));
#684=DIRECTION('',(0.,0.,1.));
#685=AXIS2_PLACEMENT_3D('',#682,#683,#684);
#686=CIRCLE('',#685,12.0700000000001);
#687=CARTESIAN_POINT('',(-10.0198512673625,0.,6.72959735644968));
#688=VERTEX_POINT('',#687);
#689=EDGE_CURVE('E612',#679,#688,#686,.T.);
#690=ORIENTED_EDGE('',*,*,#689,.T.);
#691=CARTESIAN_POINT('',(-11.6801414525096,0.,7.84469219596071));
#692=DIRECTION('',(0.,1.,0.));
#693=DIRECTION('',(0.,0.,1.));
#694=AXIS2_PLACEMENT_3D('',#691,#692,#693);
#695=CIRCLE('',#694,2.);
#696=CARTESIAN_POINT('',(-12.5479089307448,0.,6.04275446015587));
#697=VERTEX_POINT('',#696);
#698=EDGE_CURVE('E615',#688,#697,#695,.T.);
#699=ORIENTED_EDGE('',*,*,#698,.T.);
#700=DIRECTION('',(-0.900968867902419,0.,0.433883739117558));
#701=VECTOR('',#700,1.);
#702=CARTESIAN_POINT('',(-12.5479089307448,0.,6.04275446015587));
#703=LINE('',#702,#701);
#704=EDGE_CURVE('E582',#697,#642,#703,.T.);
#705=ORIENTED_EDGE('',*,*,#704,.T.);
#706=EDGE_LOOP('',(#646,#655,#664,#672,#681,#690,#699,#705));
#707=FACE_BOUND('',#706,.T.);
#708=CARTESIAN_POINT('',(28.6971305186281,0.,27.9656861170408));
#709=DIRECTION('',(0.,1.,0.));
#710=DIRECTION('',(0.,0.,1.));
#711=AXIS2_PLACEMENT_3D('',#708,#709,#710);
#712=CIRCLE('',#711,5.);
#713=CARTESIAN_POINT('',(24.7879731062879,0.,31.0831351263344));
#714=VERTEX_POINT('',#713);
#715=CARTESIAN_POINT('',(32.2780053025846,0.,31.4552900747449));
#716=VERTEX_POINT('',#715);
#717=EDGE_CURVE('E696',#714,#716,#712,.T.);
#718=ORIENTED_EDGE('',*,*,#717,.T.);
#719=CARTESIAN_POINT('',(0.,0.,0.));
#720=DIRECTION('',(0.,1.,0.));
#721=DIRECTION('',(0.,0.,1.));
#722=AXIS2_PLACEMENT_3D('',#719,#720,#721);
#723=CIRCLE('',#722,45.0700000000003);
#724=CARTESIAN_POINT('',(39.3679318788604,0.,21.9424437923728));
#725=VERTEX_POINT('',#724);
#726=EDGE_CURVE('E718',#716,#725,#723,.T.);
#727=ORIENTED_EDGE('',*,*,#726,.T.);
#728=CARTESIAN_POINT('',(35.0005109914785,0.,19.5081811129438));
#729=DIRECTION('',(0.,1.,0.));
#730=DIRECTION('',(0.,0.,-1.));
#731=AXIS2_PLACEMENT_3D('',#728,#729,#730);
#732=CIRCLE('',#731,5.);
#733=CARTESIAN_POINT('',(36.894216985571,0.,14.8806680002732));
#734=VERTEX_POINT('',#733);
#735=EDGE_CURVE('E721',#725,#734,#732,.T.);
#736=ORIENTED_EDGE('',*,*,#735,.T.);
#737=DIRECTION('',(-0.925502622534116,0.,-0.378741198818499));
#738=VECTOR('',#737,1.);
#739=CARTESIAN_POINT('',(12.9911983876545,0.,5.09889353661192));
#740=LINE('',#739,#738);
#741=CARTESIAN_POINT('',(12.9911983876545,0.,5.09889353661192));
#742=VERTEX_POINT('',#741);
#743=EDGE_CURVE('E724',#734,#742,#740,.T.);
#744=ORIENTED_EDGE('',*,*,#743,.T.);
#745=CARTESIAN_POINT('',(12.2337159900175,0.,6.94989878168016));
#746=DIRECTION('',(0.,1.,0.));
#747=DIRECTION('',(0.,0.,-1.));
#748=AXIS2_PLACEMENT_3D('',#745,#746,#747);
#749=CIRCLE('',#748,2.);
#750=CARTESIAN_POINT('',(10.4947371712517,0.,5.96199561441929));
#751=VERTEX_POINT('',#750);
#752=EDGE_CURVE('E727',#742,#751,#749,.T.);
#753=ORIENTED_EDGE('',*,*,#752,.T.);
#754=CARTESIAN_POINT('',(0.,0.,0.));
#755=DIRECTION('',(0.,-1.,0.));
#756=DIRECTION('',(0.,0.,1.));
#757=AXIS2_PLACEMENT_3D('',#754,#755,#756);
#758=CIRCLE('',#757,12.0700000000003);
#759=CARTESIAN_POINT('',(8.79049896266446,0.,8.2711563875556));
#760=VERTEX_POINT('',#759);
#761=EDGE_CURVE('E730',#751,#760,#758,.T.);
#762=ORIENTED_EDGE('',*,*,#761,.T.);
#763=CARTESIAN_POINT('',(10.2470853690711,0.,9.6416876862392));
#764=DIRECTION('',(0.,1.,0.));
#765=DIRECTION('',(0.,0.,1.));
#766=AXIS2_PLACEMENT_3D('',#763,#764,#765);
#767=CIRCLE('',#766,2.);
#768=CARTESIAN_POINT('',(8.68342240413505,0.,10.8886672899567));
#769=VERTEX_POINT('',#768);
#770=EDGE_CURVE('E733',#760,#769,#767,.T.);
#771=ORIENTED_EDGE('',*,*,#770,.T.);
#772=DIRECTION('',(0.623489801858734,0.,0.78183148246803));
#773=VECTOR('',#772,1.);
#774=CARTESIAN_POINT('',(8.68342240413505,0.,10.8886672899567));
#775=LINE('',#774,#773);
#776=EDGE_CURVE('E700',#769,#714,#775,.T.);
#777=ORIENTED_EDGE('',*,*,#776,.T.);
#778=EDGE_LOOP('',(#718,#727,#736,#744,#753,#762,#771,#777));
#779=FACE_BOUND('',#778,.T.);
#780=CARTESIAN_POINT('',(39.756822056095,0.,-5.));
#781=DIRECTION('',(0.,1.,0.));
#782=DIRECTION('',(0.,0.,1.));
#783=AXIS2_PLACEMENT_3D('',#780,#781,#782);
#784=CIRCLE('',#783,5.);
#785=CARTESIAN_POINT('',(39.756822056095,0.,0.));
#786=VERTEX_POINT('',#785);
#787=CARTESIAN_POINT('',(44.7177432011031,0.,-5.62390816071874));
#788=VERTEX_POINT('',#787);
#789=EDGE_CURVE('E772',#786,#788,#784,.T.);
#790=ORIENTED_EDGE('',*,*,#789,.T.);
#791=CARTESIAN_POINT('',(0.,0.,0.));
#792=DIRECTION('',(0.,1.,0.));
#793=DIRECTION('',(0.,0.,1.));
#794=AXIS2_PLACEMENT_3D('',#791,#792,#793);
#795=CIRCLE('',#794,45.07);
#796=CARTESIAN_POINT('',(41.7007974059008,0.,-17.0981986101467));
#797=VERTEX_POINT('',#796);
#798=EDGE_CURVE('E794',#788,#797,#795,.T.);
#799=ORIENTED_EDGE('',*,*,#798,.T.);
#800=CARTESIAN_POINT('',(37.0745718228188,0.,-15.2013494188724));
#801=DIRECTION('',(0.,1.,0.));
#802=DIRECTION('',(0.,0.,-1.));
#803=AXIS2_PLACEMENT_3D('',#800,#801,#802);
#804=CIRCLE('',#803,5.);
#805=CARTESIAN_POINT('',(34.6373427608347,0.,-19.56711561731));
#806=VERTEX_POINT('',#805);
#807=EDGE_CURVE('E797',#797,#806,#804,.T.);
#808=ORIENTED_EDGE('',*,*,#807,.T.);
#809=DIRECTION('',(-0.87315323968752,0.,0.487445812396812));
#810=VECTOR('',#809,1.);
#811=CARTESIAN_POINT('',(12.0863552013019,0.,-6.977819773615));
#812=LINE('',#811,#810);
#813=CARTESIAN_POINT('',(12.0863552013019,0.,-6.977819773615));
#814=VERTEX_POINT('',#813);
#815=EDGE_CURVE('E800',#806,#814,#812,.T.);
#816=ORIENTED_EDGE('',*,*,#815,.T.);
#817=CARTESIAN_POINT('',(13.0612468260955,0.,-5.23151329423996));
#818=DIRECTION('',(0.,1.,0.));
#819=DIRECTION('',(0.,0.,-1.));
#820=AXIS2_PLACEMENT_3D('',#817,#818,#819);
#821=CIRCLE('',#820,2.);
#822=CARTESIAN_POINT('',(11.2046374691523,0.,-4.4878724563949));
#823=VERTEX_POINT('',#822);
#824=EDGE_CURVE('E803',#814,#823,#821,.T.);
#825=ORIENTED_EDGE('',*,*,#824,.T.);
#826=CARTESIAN_POINT('',(0.,0.,0.));
#827=DIRECTION('',(0.,-1.,0.));
#828=DIRECTION('',(0.,0.,1.));
#829=AXIS2_PLACEMENT_3D('',#826,#827,#828);
#830=CIRCLE('',#829,12.07);
#831=CARTESIAN_POINT('',(11.9474369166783,0.,-1.71570717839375));
#832=VERTEX_POINT('',#831);
#833=EDGE_CURVE('E806',#823,#832,#830,.T.);
#834=ORIENTED_EDGE('',*,*,#833,.T.);
#835=CARTESIAN_POINT('',(13.9271282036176,0.,-2.));
#836=DIRECTION('',(0.,1.,0.));
#837=DIRECTION('',(0.,0.,1.));
#838=AXIS2_PLACEMENT_3D('',#835,#836,#837);
#839=CIRCLE('',#838,2.);
#840=CARTESIAN_POINT('',(13.9271282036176,0.,0.));
#841=VERTEX_POINT('',#840);
#842=EDGE_CURVE('E809',#832,#841,#839,.T.);
#843=ORIENTED_EDGE('',*,*,#842,.T.);
#844=DIRECTION('',(1.,0.,0.));
#845=VECTOR('',#844,1.);
#846=CARTESIAN_POINT('',(13.9271282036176,0.,0.));
#847=LINE('',#846,#845);
#848=EDGE_CURVE('E776',#841,#786,#847,.T.);
#849=ORIENTED_EDGE('',*,*,#848,.T.);
#850=EDGE_LOOP('',(#790,#799,#808,#816,#825,#834,#843,#849));
#851=FACE_BOUND('',#850,.T.);
#852=CARTESIAN_POINT('',(0.,0.,0.));
#853=DIRECTION('',(0.,1.,0.));
#854=DIRECTION('',(0.,0.,1.));
#855=AXIS2_PLACEMENT_3D('',#852,#853,#854);
#856=CIRCLE('',#855,50.8);
#857=CARTESIAN_POINT('',(0.,0.,50.8));
#858=VERTEX_POINT('',#857);
#859=EDGE_CURVE('E35',#858,#858,#856,.T.);
#860=ORIENTED_EDGE('',*,*,#859,.F.);
#861=EDGE_LOOP('',(#860));
#862=FACE_BOUND('',#861,.T.);
#863=CARTESIAN_POINT('',(0.,0.,0.));
#864=DIRECTION('',(0.,1.,0.));
#865=DIRECTION('',(0.,0.,1.));
#866=AXIS2_PLACEMENT_3D('',#863,#864,#865);
#867=CIRCLE('',#866,3.07);
#868=CARTESIAN_POINT('',(-1.83187666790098,0.,-2.46356));
#869=VERTEX_POINT('',#868);
#870=CARTESIAN_POINT('',(1.83187666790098,0.,-2.46356));
#871=VERTEX_POINT('',#870);
#872=EDGE_CURVE('E755',#869,#871,#867,.T.);
#873=ORIENTED_EDGE('',*,*,#872,.T.);
#874=DIRECTION('',(-1.,0.,0.));
#875=VECTOR('',#874,1.);
#876=CARTESIAN_POINT('',(1.83187666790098,0.,-2.46356));
#877=LINE('',#876,#875);
#878=EDGE_CURVE('E760',#871,#869,#877,.T.);
#879=ORIENTED_EDGE('',*,*,#878,.T.);
#880=EDGE_LOOP('',(#873,#879));
#881=FACE_BOUND('',#880,.T.);
#882=CARTESIAN_POINT('',(-3.9720856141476,0.,39.8726401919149));
#883=DIRECTION('',(0.,1.,0.));
#884=DIRECTION('',(0.,0.,1.));
#885=AXIS2_PLACEMENT_3D('',#882,#883,#884);
#886=CIRCLE('',#885,5.);
#887=CARTESIAN_POINT('',(-8.84672517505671,0.,38.7600355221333));
#888=VERTEX_POINT('',#887);
#889=CARTESIAN_POINT('',(-4.46772894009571,0.,44.8480133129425));
#890=VERTEX_POINT('',#889);
#891=EDGE_CURVE('E637',#888,#890,#886,.T.);
#892=ORIENTED_EDGE('',*,*,#891,.T.);
#893=CARTESIAN_POINT('',(0.,0.,0.));
#894=DIRECTION('',(0.,1.,0.));
#895=DIRECTION('',(0.,0.,1.));
#896=AXIS2_PLACEMENT_3D('',#893,#894,#895);
#897=CIRCLE('',#896,45.0700000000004);
#898=CARTESIAN_POINT('',(7.39021068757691,0.,44.4599784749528));
#899=VERTEX_POINT('',#898);
#900=EDGE_CURVE('E659',#890,#899,#897,.T.);
#901=ORIENTED_EDGE('',*,*,#900,.T.);
#902=CARTESIAN_POINT('',(6.57035150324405,0.,39.5276533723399));
#903=DIRECTION('',(0.,1.,0.));
#904=DIRECTION('',(0.,0.,-1.));
#905=AXIS2_PLACEMENT_3D('',#902,#903,#904);
#906=CIRCLE('',#905,5.);
#907=CARTESIAN_POINT('',(11.368993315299,0.,38.1230051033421));
#908=VERTEX_POINT('',#907);
#909=EDGE_CURVE('E662',#899,#908,#906,.T.);
#910=ORIENTED_EDGE('',*,*,#909,.T.);
#911=DIRECTION('',(-0.280929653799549,0.,-0.959728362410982));
#912=VECTOR('',#911,1.);
#913=CARTESIAN_POINT('',(4.11340421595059,0.,13.3360360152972));
#914=LINE('',#913,#912);
#915=CARTESIAN_POINT('',(4.1134042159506,0.,13.3360360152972));
#916=VERTEX_POINT('',#915);
#917=EDGE_CURVE('E665',#908,#916,#914,.T.);
#918=ORIENTED_EDGE('',*,*,#917,.T.);
#919=CARTESIAN_POINT('',(2.19394749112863,0.,13.8978953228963));
#920=DIRECTION('',(0.,1.,0.));
#921=DIRECTION('',(0.,0.,-1.));
#922=AXIS2_PLACEMENT_3D('',#919,#920,#921);
#923=CIRCLE('',#922,2.);
#924=CARTESIAN_POINT('',(1.88208572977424,0.,11.922359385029));
#925=VERTEX_POINT('',#924);
#926=EDGE_CURVE('E668',#916,#925,#923,.T.);
#927=ORIENTED_EDGE('',*,*,#926,.T.);
#928=CARTESIAN_POINT('',(0.,0.,0.));
#929=DIRECTION('',(0.,-1.,0.));
#930=DIRECTION('',(0.,0.,1.));
#931=AXIS2_PLACEMENT_3D('',#928,#929,#930);
#932=CIRCLE('',#931,12.0700000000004);
#933=CARTESIAN_POINT('',(-0.98586400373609,0.,12.0296704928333));
#934=VERTEX_POINT('',#933);
#935=EDGE_CURVE('E671',#925,#934,#932,.T.);
#936=ORIENTED_EDGE('',*,*,#935,.T.);
#937=CARTESIAN_POINT('',(-1.14922175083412,0.,14.0229878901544));
#938=DIRECTION('',(0.,1.,0.));
#939=DIRECTION('',(0.,0.,1.));
#940=AXIS2_PLACEMENT_3D('',#937,#938,#939);
#941=CIRCLE('',#940,2.);
#942=CARTESIAN_POINT('',(-3.09907757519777,0.,13.5779460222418));
#943=VERTEX_POINT('',#942);
#944=EDGE_CURVE('E674',#934,#943,#941,.T.);
#945=ORIENTED_EDGE('',*,*,#944,.T.);
#946=DIRECTION('',(-0.222520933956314,0.,0.974927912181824));
#947=VECTOR('',#946,1.);
#948=CARTESIAN_POINT('',(-3.09907757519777,0.,13.5779460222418));
#949=LINE('',#948,#947);
#950=EDGE_CURVE('E641',#943,#888,#949,.T.);
#951=ORIENTED_EDGE('',*,*,#950,.T.);
#952=EDGE_LOOP('',(#892,#901,#910,#918,#927,#936,#945,#951));
#953=FACE_BOUND('',#952,.T.);
#954=CARTESIAN_POINT('',(-37.9890776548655,0.,-12.744994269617));
#955=DIRECTION('',(0.,1.,0.));
#956=DIRECTION('',(0.,0.,1.));
#957=AXIS2_PLACEMENT_3D('',#954,#955,#956);
#958=CIRCLE('',#957,5.);
#959=CARTESIAN_POINT('',(-35.8196589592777,0.,-17.2498386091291));
#960=VERTEX_POINT('',#959);
#961=CARTESIAN_POINT('',(-42.7294167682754,0.,-14.3353354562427));
#962=VERTEX_POINT('',#961);
#963=EDGE_CURVE('E519',#960,#962,#958,.T.);
#964=ORIENTED_EDGE('',*,*,#963,.T.);
#965=CARTESIAN_POINT('',(0.,0.,0.));
#966=DIRECTION('',(0.,1.,0.));
#967=DIRECTION('',(0.,0.,1.));
#968=AXIS2_PLACEMENT_3D('',#965,#966,#967);
#969=CIRCLE('',#968,45.0699999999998);
#970=CARTESIAN_POINT('',(-44.9897505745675,0.,-2.68835325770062));
#971=VERTEX_POINT('',#970);
#972=EDGE_CURVE('E541',#962,#971,#969,.T.);
#973=ORIENTED_EDGE('',*,*,#972,.T.);
#974=CARTESIAN_POINT('',(-39.9986533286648,0.,-2.39011127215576));
#975=DIRECTION('',(0.,1.,0.));
#976=DIRECTION('',(0.,0.,-1.));
#977=AXIS2_PLACEMENT_3D('',#974,#975,#976);
#978=CIRCLE('',#977,5.);
#979=CARTESIAN_POINT('',(-39.6970207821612,0.,2.60078221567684));
#980=VERTEX_POINT('',#979);
#981=EDGE_CURVE('E544',#971,#980,#978,.T.);
#982=ORIENTED_EDGE('',*,*,#981,.T.);
#983=DIRECTION('',(0.998178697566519,0.,-0.0603265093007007));
#984=VECTOR('',#983,1.);
#985=CARTESIAN_POINT('',(-13.9169922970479,0.,1.04272539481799));
#986=LINE('',#985,#984);
#987=CARTESIAN_POINT('',(-13.9169922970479,0.,1.042725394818));
#988=VERTEX_POINT('',#987);
#989=EDGE_CURVE('E547',#980,#988,#986,.T.);
#990=ORIENTED_EDGE('',*,*,#989,.T.);
#991=CARTESIAN_POINT('',(-14.0376453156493,0.,-0.953632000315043));
#992=DIRECTION('',(0.,1.,0.));
#993=DIRECTION('',(0.,0.,-1.));
#994=AXIS2_PLACEMENT_3D('',#991,#992,#993);
#995=CIRCLE('',#994,2.);
#996=CARTESIAN_POINT('',(-12.0422444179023,0.,-0.818076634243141));
#997=VERTEX_POINT('',#996);
#998=EDGE_CURVE('E550',#988,#997,#995,.T.);
#999=ORIENTED_EDGE('',*,*,#998,.T.);
#1000=CARTESIAN_POINT('',(0.,0.,0.));
#1001=DIRECTION('',(0.,-1.,0.));
#1002=DIRECTION('',(0.,0.,1.));
#1003=AXIS2_PLACEMENT_3D('',#1000,#1001,#1002);
#1004=CIRCLE('',#1003,12.0699999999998);
#1005=CARTESIAN_POINT('',(-11.5086861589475,0.,-3.63799984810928));
#1006=VERTEX_POINT('',#1005);
#1007=EDGE_CURVE('E553',#997,#1006,#1004,.T.);
#1008=ORIENTED_EDGE('',*,*,#1007,.T.);
#1009=CARTESIAN_POINT('',(-13.4156764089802,0.,-4.24081672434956));
#1010=DIRECTION('',(0.,1.,0.));
#1011=DIRECTION('',(0.,0.,1.));
#1012=AXIS2_PLACEMENT_3D('',#1009,#1010,#1011);
#1013=CIRCLE('',#1012,2.);
#1014=CARTESIAN_POINT('',(-12.5479089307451,0.,-6.0427544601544));
#1015=VERTEX_POINT('',#1014);
#1016=EDGE_CURVE('E556',#1006,#1015,#1013,.T.);
#1017=ORIENTED_EDGE('',*,*,#1016,.T.);
#1018=DIRECTION('',(-0.900968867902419,0.,-0.433883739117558));
#1019=VECTOR('',#1018,1.);
#1020=CARTESIAN_POINT('',(-12.5479089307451,0.,-6.0427544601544));
#1021=LINE('',#1020,#1019);
#1022=EDGE_CURVE('E523',#1015,#960,#1021,.T.);
#1023=ORIENTED_EDGE('',*,*,#1022,.T.);
#1024=EDGE_LOOP('',(#964,#973,#982,#990,#999,#1008,#1017,#1023));
#1025=FACE_BOUND('',#1024,.T.);
#1026=CARTESIAN_POINT('',(20.8788156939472,0.,-34.2005841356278));
#1027=DIRECTION('',(0.,1.,0.));
#1028=DIRECTION('',(0.,0.,1.));
#1029=AXIS2_PLACEMENT_3D('',#1026,#1027,#1028);
#1030=CIRCLE('',#1029,5.);
#1031=CARTESIAN_POINT('',(24.7879731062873,0.,-31.0831351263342));
#1032=VERTEX_POINT('',#1031);
#1033=CARTESIAN_POINT('',(23.4841083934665,0.,-38.4681888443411));
#1034=VERTEX_POINT('',#1033);
#1035=EDGE_CURVE('E54',#1032,#1034,#1030,.T.);
#1036=ORIENTED_EDGE('',*,*,#1035,.T.);
#1037=CARTESIAN_POINT('',(0.,0.,0.));
#1038=DIRECTION('',(0.,1.,0.));
#1039=DIRECTION('',(0.,0.,1.));
#1040=AXIS2_PLACEMENT_3D('',#1037,#1038,#1039);
#1041=CIRCLE('',#1040,45.0699999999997);
#1042=CARTESIAN_POINT('',(12.6321119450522,0.,-43.2635487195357));
#1043=VERTEX_POINT('',#1042);
#1044=EDGE_CURVE('E411',#1034,#1043,#1041,.T.);
#1045=ORIENTED_EDGE('',*,*,#1044,.T.);
#1046=CARTESIAN_POINT('',(11.2307238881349,0.,-38.4639537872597));
#1047=DIRECTION('',(0.,1.,0.));
#1048=DIRECTION('',(0.,0.,-1.));
#1049=AXIS2_PLACEMENT_3D('',#1046,#1047,#1048);
#1050=CIRCLE('',#1049,5.);
#1051=CARTESIAN_POINT('',(6.29784296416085,0.,-39.28046207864));
#1052=VERTEX_POINT('',#1051);
#1053=EDGE_CURVE('E433',#1043,#1052,#1050,.T.);
#1054=ORIENTED_EDGE('',*,*,#1053,.T.);
#1055=DIRECTION('',(-0.16330165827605,0.,0.986576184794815));
#1056=VECTOR('',#1055,1.);
#1057=CARTESIAN_POINT('',(2.0802400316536,0.,-13.800092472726));
#1058=LINE('',#1057,#1056);
#1059=CARTESIAN_POINT('',(2.0802400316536,0.,-13.800092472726));
#1060=VERTEX_POINT('',#1059);
#1061=EDGE_CURVE('E436',#1052,#1060,#1058,.T.);
#1062=ORIENTED_EDGE('',*,*,#1061,.T.);
#1063=CARTESIAN_POINT('',(4.05339240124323,0.,-13.4734891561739));
#1064=DIRECTION('',(0.,1.,0.));
#1065=DIRECTION('',(0.,0.,-1.));
#1066=AXIS2_PLACEMENT_3D('',#1063,#1064,#1065);
#1067=CIRCLE('',#1066,2.);
#1068=CARTESIAN_POINT('',(3.47721721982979,0.,-11.5582810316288));
#1069=VERTEX_POINT('',#1068);
#1070=EDGE_CURVE('E439',#1060,#1069,#1067,.T.);
#1071=ORIENTED_EDGE('',*,*,#1070,.T.);
#1072=CARTESIAN_POINT('',(0.,0.,0.));
#1073=DIRECTION('',(0.,-1.,0.));
#1074=DIRECTION('',(0.,0.,1.));
#1075=AXIS2_PLACEMENT_3D('',#1072,#1073,#1074);
#1076=CIRCLE('',#1075,12.0699999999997);
#1077=CARTESIAN_POINT('',(6.10771118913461,0.,-10.410608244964));
#1078=VERTEX_POINT('',#1077);
#1079=EDGE_CURVE('E442',#1069,#1078,#1076,.T.);
#1080=ORIENTED_EDGE('',*,*,#1079,.T.);
#1081=CARTESIAN_POINT('',(7.11975943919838,0.,-12.1356468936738));
#1082=DIRECTION('',(0.,1.,0.));
#1083=DIRECTION('',(0.,0.,1.));
#1084=AXIS2_PLACEMENT_3D('',#1081,#1082,#1083);
#1085=CIRCLE('',#1084,2.);
#1086=CARTESIAN_POINT('',(8.68342240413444,0.,-10.8886672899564));
#1087=VERTEX_POINT('',#1086);
#1088=EDGE_CURVE('E445',#1078,#1087,#1085,.T.);
#1089=ORIENTED_EDGE('',*,*,#1088,.T.);
#1090=DIRECTION('',(0.623489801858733,0.,-0.78183148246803));
#1091=VECTOR('',#1090,1.);
#1092=CARTESIAN_POINT('',(8.68342240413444,0.,-10.8886672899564));
#1093=LINE('',#1092,#1091);
#1094=EDGE_CURVE('E405',#1087,#1032,#1093,.T.);
#1095=ORIENTED_EDGE('',*,*,#1094,.T.);
#1096=EDGE_LOOP('',(#1036,#1045,#1054,#1062,#1071,#1080,#1089,#1095));
#1097=FACE_BOUND('',#1096,.T.);
#1098=ADVANCED_FACE('F836',(#635,#707,#779,#851,#862,#881,#953,#1025,#1097),#563,.F.);
#1099=CARTESIAN_POINT('',(0.,6.35,0.));
#1100=DIRECTION('',(0.,-1.,0.));
#1101=DIRECTION('',(0.,0.,-1.));
#1102=AXIS2_PLACEMENT_3D('',#1099,#1100,#1101);
#1103=CYLINDRICAL_SURFACE('',#1102,50.8);
#1104=ORIENTED_EDGE('',*,*,#319,.F.);
#1105=EDGE_LOOP('',(#1104));
#1106=FACE_BOUND('',#1105,.T.);
#1107=ORIENTED_EDGE('',*,*,#859,.T.);
#1108=EDGE_LOOP('',(#1107));
#1109=FACE_BOUND('',#1108,.T.);
#1110=ADVANCED_FACE('F33',(#1106,#1109),#1103,.T.);
#1111=CARTESIAN_POINT('',(39.756822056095,6.35,-5.));
#1112=DIRECTION('',(0.,-1.,0.));
#1113=DIRECTION('',(0.,0.,-1.));
#1114=AXIS2_PLACEMENT_3D('',#1111,#1112,#1113);
#1115=CYLINDRICAL_SURFACE('',#1114,5.);
#1116=ORIENTED_EDGE('',*,*,#789,.F.);
#1117=DIRECTION('',(0.,-1.,0.));
#1118=VECTOR('',#1117,1.);
#1119=CARTESIAN_POINT('',(39.756822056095,6.35,0.));
#1120=LINE('',#1119,#1118);
#1121=EDGE_CURVE('E791',#257,#786,#1120,.T.);
#1122=ORIENTED_EDGE('',*,*,#1121,.F.);
#1123=ORIENTED_EDGE('',*,*,#258,.T.);
#1124=DIRECTION('',(0.,-1.,0.));
#1125=VECTOR('',#1124,1.);
#1126=CARTESIAN_POINT('',(44.7177432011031,6.35,-5.62390816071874));
#1127=LINE('',#1126,#1125);
#1128=EDGE_CURVE('E828',#246,#788,#1127,.T.);
#1129=ORIENTED_EDGE('',*,*,#1128,.T.);
#1130=EDGE_LOOP('',(#1116,#1122,#1123,#1129));
#1131=FACE_BOUND('',#1130,.T.);
#1132=ADVANCED_FACE('F882',(#1131),#1115,.F.);
#1133=CARTESIAN_POINT('',(0.,6.35,0.));
#1134=DIRECTION('',(0.,-1.,0.));
#1135=DIRECTION('',(0.,0.,-1.));
#1136=AXIS2_PLACEMENT_3D('',#1133,#1134,#1135);
#1137=CYLINDRICAL_SURFACE('',#1136,45.07);
#1138=ORIENTED_EDGE('',*,*,#798,.F.);
#1139=ORIENTED_EDGE('',*,*,#1128,.F.);
#1140=ORIENTED_EDGE('',*,*,#249,.T.);
#1141=DIRECTION('',(0.,-1.,0.));
#1142=VECTOR('',#1141,1.);
#1143=CARTESIAN_POINT('',(41.7007974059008,6.35,-17.0981986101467));
#1144=LINE('',#1143,#1142);
#1145=EDGE_CURVE('E826',#248,#797,#1144,.T.);
#1146=ORIENTED_EDGE('',*,*,#1145,.T.);
#1147=EDGE_LOOP('',(#1138,#1139,#1140,#1146));
#1148=FACE_BOUND('',#1147,.T.);
#1149=ADVANCED_FACE('F885',(#1148),#1137,.F.);
#1150=CARTESIAN_POINT('',(37.0745718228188,6.35,-15.2013494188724));
#1151=DIRECTION('',(0.,-1.,0.));
#1152=DIRECTION('',(0.,0.,-1.));
#1153=AXIS2_PLACEMENT_3D('',#1150,#1151,#1152);
#1154=CYLINDRICAL_SURFACE('',#1153,5.);
#1155=ORIENTED_EDGE('',*,*,#807,.F.);
#1156=ORIENTED_EDGE('',*,*,#1145,.F.);
#1157=ORIENTED_EDGE('',*,*,#308,.T.);
#1158=DIRECTION('',(0.,-1.,0.));
#1159=VECTOR('',#1158,1.);
#1160=CARTESIAN_POINT('',(34.6373427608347,6.35,-19.56711561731));
#1161=LINE('',#1160,#1159);
#1162=EDGE_CURVE('E824',#300,#806,#1161,.T.);
#1163=ORIENTED_EDGE('',*,*,#1162,.T.);
#1164=EDGE_LOOP('',(#1155,#1156,#1157,#1163));
#1165=FACE_BOUND('',#1164,.T.);
#1166=ADVANCED_FACE('F888',(#1165),#1154,.F.);
#1167=CARTESIAN_POINT('',(12.0863552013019,6.35,-6.977819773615));
#1168=DIRECTION('',(0.487445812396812,0.,0.87315323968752));
#1169=DIRECTION('',(0.87315323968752,0.,-0.487445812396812));
#1170=AXIS2_PLACEMENT_3D('',#1167,#1168,#1169);
#1171=PLANE('',#1170);
#1172=ORIENTED_EDGE('',*,*,#815,.F.);
#1173=ORIENTED_EDGE('',*,*,#1162,.F.);
#1174=ORIENTED_EDGE('',*,*,#301,.T.);
#1175=DIRECTION('',(0.,-1.,0.));
#1176=VECTOR('',#1175,1.);
#1177=CARTESIAN_POINT('',(12.0863552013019,6.35,-6.977819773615));
#1178=LINE('',#1177,#1176);
#1179=EDGE_CURVE('E822',#292,#814,#1178,.T.);
#1180=ORIENTED_EDGE('',*,*,#1179,.T.);
#1181=EDGE_LOOP('',(#1172,#1173,#1174,#1180));
#1182=FACE_BOUND('',#1181,.T.);
#1183=ADVANCED_FACE('F892',(#1182),#1171,.T.);
#1184=CARTESIAN_POINT('',(13.0612468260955,6.35,-5.23151329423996));
#1185=DIRECTION('',(0.,-1.,0.));
#1186=DIRECTION('',(0.,0.,-1.));
#1187=AXIS2_PLACEMENT_3D('',#1184,#1185,#1186);
#1188=CYLINDRICAL_SURFACE('',#1187,2.);
#1189=ORIENTED_EDGE('',*,*,#824,.F.);
#1190=ORIENTED_EDGE('',*,*,#1179,.F.);
#1191=ORIENTED_EDGE('',*,*,#293,.T.);
#1192=DIRECTION('',(0.,-1.,0.));
#1193=VECTOR('',#1192,1.);
#1194=CARTESIAN_POINT('',(11.2046374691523,6.35,-4.4878724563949));
#1195=LINE('',#1194,#1193);
#1196=EDGE_CURVE('E820',#283,#823,#1195,.T.);
#1197=ORIENTED_EDGE('',*,*,#1196,.T.);
#1198=EDGE_LOOP('',(#1189,#1190,#1191,#1197));
#1199=FACE_BOUND('',#1198,.T.);
#1200=ADVANCED_FACE('F896',(#1199),#1188,.F.);
#1201=CARTESIAN_POINT('',(0.,6.35,0.));
#1202=DIRECTION('',(0.,-1.,0.));
#1203=DIRECTION('',(0.,0.,-1.));
#1204=AXIS2_PLACEMENT_3D('',#1201,#1202,#1203);
#1205=CYLINDRICAL_SURFACE('',#1204,12.07);
#1206=ORIENTED_EDGE('',*,*,#833,.F.);
#1207=ORIENTED_EDGE('',*,*,#1196,.F.);
#1208=ORIENTED_EDGE('',*,*,#284,.T.);
#1209=DIRECTION('',(0.,-1.,0.));
#1210=VECTOR('',#1209,1.);
#1211=CARTESIAN_POINT('',(11.9474369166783,6.35,-1.71570717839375));
#1212=LINE('',#1211,#1210);
#1213=EDGE_CURVE('E818',#274,#832,#1212,.T.);
#1214=ORIENTED_EDGE('',*,*,#1213,.T.);
#1215=EDGE_LOOP('',(#1206,#1207,#1208,#1214));
#1216=FACE_BOUND('',#1215,.T.);
#1217=ADVANCED_FACE('F900',(#1216),#1205,.T.);
#1218=CARTESIAN_POINT('',(13.9271282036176,6.35,-2.));
#1219=DIRECTION('',(0.,-1.,0.));
#1220=DIRECTION('',(0.,0.,-1.));
#1221=AXIS2_PLACEMENT_3D('',#1218,#1219,#1220);
#1222=CYLINDRICAL_SURFACE('',#1221,2.);
#1223=ORIENTED_EDGE('',*,*,#842,.F.);
#1224=ORIENTED_EDGE('',*,*,#1213,.F.);
#1225=ORIENTED_EDGE('',*,*,#275,.T.);
#1226=DIRECTION('',(0.,-1.,0.));
#1227=VECTOR('',#1226,1.);
#1228=CARTESIAN_POINT('',(13.9271282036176,6.35,0.));
#1229=LINE('',#1228,#1227);
#1230=EDGE_CURVE('E816',#265,#841,#1229,.T.);
#1231=ORIENTED_EDGE('',*,*,#1230,.T.);
#1232=EDGE_LOOP('',(#1223,#1224,#1225,#1231));
#1233=FACE_BOUND('',#1232,.T.);
#1234=ADVANCED_FACE('F904',(#1233),#1222,.F.);
#1235=CARTESIAN_POINT('',(13.9271282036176,6.35,0.));
#1236=DIRECTION('',(0.,0.,-1.));
#1237=DIRECTION('',(-1.,0.,0.));
#1238=AXIS2_PLACEMENT_3D('',#1235,#1236,#1237);
#1239=PLANE('',#1238);
#1240=ORIENTED_EDGE('',*,*,#848,.F.);
#1241=ORIENTED_EDGE('',*,*,#1230,.F.);
#1242=ORIENTED_EDGE('',*,*,#266,.T.);
#1243=ORIENTED_EDGE('',*,*,#1121,.T.);
#1244=EDGE_LOOP('',(#1240,#1241,#1242,#1243));
#1245=FACE_BOUND('',#1244,.T.);
#1246=ADVANCED_FACE('F908',(#1245),#1239,.T.);
#1247=CARTESIAN_POINT('',(0.,6.35,0.));
#1248=DIRECTION('',(0.,-1.,0.));
#1249=DIRECTION('',(0.,0.,-1.));
#1250=AXIS2_PLACEMENT_3D('',#1247,#1248,#1249);
#1251=CYLINDRICAL_SURFACE('',#1250,3.07);
#1252=ORIENTED_EDGE('',*,*,#872,.F.);
#1253=DIRECTION('',(0.,-1.,0.));
#1254=VECTOR('',#1253,1.);
#1255=CARTESIAN_POINT('',(-1.83187666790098,6.35,-2.46356));
#1256=LINE('',#1255,#1254);
#1257=EDGE_CURVE('E762',#330,#869,#1256,.T.);
#1258=ORIENTED_EDGE('',*,*,#1257,.F.);
#1259=ORIENTED_EDGE('',*,*,#338,.T.);
#1260=DIRECTION('',(0.,-1.,0.));
#1261=VECTOR('',#1260,1.);
#1262=CARTESIAN_POINT('',(1.83187666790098,6.35,-2.46356));
#1263=LINE('',#1262,#1261);
#1264=EDGE_CURVE('E769',#328,#871,#1263,.T.);
#1265=ORIENTED_EDGE('',*,*,#1264,.T.);
#1266=EDGE_LOOP('',(#1252,#1258,#1259,#1265));
#1267=FACE_BOUND('',#1266,.T.);
#1268=ADVANCED_FACE('F912',(#1267),#1251,.F.);
#1269=CARTESIAN_POINT('',(1.83187666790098,6.35,-2.46356));
#1270=DIRECTION('',(0.,0.,1.));
#1271=DIRECTION('',(1.,0.,0.));
#1272=AXIS2_PLACEMENT_3D('',#1269,#1270,#1271);
#1273=PLANE('',#1272);
#1274=ORIENTED_EDGE('',*,*,#878,.F.);
#1275=ORIENTED_EDGE('',*,*,#1264,.F.);
#1276=ORIENTED_EDGE('',*,*,#331,.T.);
#1277=ORIENTED_EDGE('',*,*,#1257,.T.);
#1278=EDGE_LOOP('',(#1274,#1275,#1276,#1277));
#1279=FACE_BOUND('',#1278,.T.);
#1280=ADVANCED_FACE('F916',(#1279),#1273,.T.);
#1281=CARTESIAN_POINT('',(28.6971305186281,6.35,27.9656861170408));
#1282=DIRECTION('',(0.,-1.,0.));
#1283=DIRECTION('',(0.,0.,-1.));
#1284=AXIS2_PLACEMENT_3D('',#1281,#1282,#1283);
#1285=CYLINDRICAL_SURFACE('',#1284,5.);
#1286=ORIENTED_EDGE('',*,*,#717,.F.);
#1287=DIRECTION('',(0.,-1.,0.));
#1288=VECTOR('',#1287,1.);
#1289=CARTESIAN_POINT('',(24.7879731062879,6.35,31.0831351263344));
#1290=LINE('',#1289,#1288);
#1291=EDGE_CURVE('E715',#185,#714,#1290,.T.);
#1292=ORIENTED_EDGE('',*,*,#1291,.F.);
#1293=ORIENTED_EDGE('',*,*,#186,.T.);
#1294=DIRECTION('',(0.,-1.,0.));
#1295=VECTOR('',#1294,1.);
#1296=CARTESIAN_POINT('',(32.2780053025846,6.35,31.4552900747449));
#1297=LINE('',#1296,#1295);
#1298=EDGE_CURVE('E752',#174,#716,#1297,.T.);
#1299=ORIENTED_EDGE('',*,*,#1298,.T.);
#1300=EDGE_LOOP('',(#1286,#1292,#1293,#1299));
#1301=FACE_BOUND('',#1300,.T.);
#1302=ADVANCED_FACE('F920',(#1301),#1285,.F.);
#1303=CARTESIAN_POINT('',(0.,6.35,0.));
#1304=DIRECTION('',(0.,-1.,0.));
#1305=DIRECTION('',(0.,0.,-1.));
#1306=AXIS2_PLACEMENT_3D('',#1303,#1304,#1305);
#1307=CYLINDRICAL_SURFACE('',#1306,45.0700000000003);
#1308=ORIENTED_EDGE('',*,*,#726,.F.);
#1309=ORIENTED_EDGE('',*,*,#1298,.F.);
#1310=ORIENTED_EDGE('',*,*,#177,.T.);
#1311=DIRECTION('',(0.,-1.,0.));
#1312=VECTOR('',#1311,1.);
#1313=CARTESIAN_POINT('',(39.3679318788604,6.35,21.9424437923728));
#1314=LINE('',#1313,#1312);
#1315=EDGE_CURVE('E750',#176,#725,#1314,.T.);
#1316=ORIENTED_EDGE('',*,*,#1315,.T.);
#1317=EDGE_LOOP('',(#1308,#1309,#1310,#1316));
#1318=FACE_BOUND('',#1317,.T.);
#1319=ADVANCED_FACE('F924',(#1318),#1307,.F.);
#1320=CARTESIAN_POINT('',(35.0005109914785,6.35,19.5081811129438));
#1321=DIRECTION('',(0.,-1.,0.));
#1322=DIRECTION('',(0.,0.,-1.));
#1323=AXIS2_PLACEMENT_3D('',#1320,#1321,#1322);
#1324=CYLINDRICAL_SURFACE('',#1323,5.);
#1325=ORIENTED_EDGE('',*,*,#735,.F.);
#1326=ORIENTED_EDGE('',*,*,#1315,.F.);
#1327=ORIENTED_EDGE('',*,*,#236,.T.);
#1328=DIRECTION('',(0.,-1.,0.));
#1329=VECTOR('',#1328,1.);
#1330=CARTESIAN_POINT('',(36.894216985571,6.35,14.8806680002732));
#1331=LINE('',#1330,#1329);
#1332=EDGE_CURVE('E748',#228,#734,#1331,.T.);
#1333=ORIENTED_EDGE('',*,*,#1332,.T.);
#1334=EDGE_LOOP('',(#1325,#1326,#1327,#1333));
#1335=FACE_BOUND('',#1334,.T.);
#1336=ADVANCED_FACE('F928',(#1335),#1324,.F.);
#1337=CARTESIAN_POINT('',(12.9911983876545,6.35,5.09889353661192));
#1338=DIRECTION('',(-0.378741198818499,0.,0.925502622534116));
#1339=DIRECTION('',(0.925502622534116,0.,0.378741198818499));
#1340=AXIS2_PLACEMENT_3D('',#1337,#1338,#1339);
#1341=PLANE('',#1340);
#1342=ORIENTED_EDGE('',*,*,#743,.F.);
#1343=ORIENTED_EDGE('',*,*,#1332,.F.);
#1344=ORIENTED_EDGE('',*,*,#229,.T.);
#1345=DIRECTION('',(0.,-1.,0.));
#1346=VECTOR('',#1345,1.);
#1347=CARTESIAN_POINT('',(12.9911983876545,6.35,5.09889353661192));
#1348=LINE('',#1347,#1346);
#1349=EDGE_CURVE('E746',#220,#742,#1348,.T.);
#1350=ORIENTED_EDGE('',*,*,#1349,.T.);
#1351=EDGE_LOOP('',(#1342,#1343,#1344,#1350));
#1352=FACE_BOUND('',#1351,.T.);
#1353=ADVANCED_FACE('F932',(#1352),#1341,.T.);
#1354=CARTESIAN_POINT('',(12.2337159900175,6.35,6.94989878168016));
#1355=DIRECTION('',(0.,-1.,0.));
#1356=DIRECTION('',(0.,0.,-1.));
#1357=AXIS2_PLACEMENT_3D('',#1354,#1355,#1356);
#1358=CYLINDRICAL_SURFACE('',#1357,2.);
#1359=ORIENTED_EDGE('',*,*,#752,.F.);
#1360=ORIENTED_EDGE('',*,*,#1349,.F.);
#1361=ORIENTED_EDGE('',*,*,#221,.T.);
#1362=DIRECTION('',(0.,-1.,0.));
#1363=VECTOR('',#1362,1.);
#1364=CARTESIAN_POINT('',(10.4947371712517,6.35,5.96199561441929));
#1365=LINE('',#1364,#1363);
#1366=EDGE_CURVE('E744',#211,#751,#1365,.T.);
#1367=ORIENTED_EDGE('',*,*,#1366,.T.);
#1368=EDGE_LOOP('',(#1359,#1360,#1361,#1367));
#1369=FACE_BOUND('',#1368,.T.);
#1370=ADVANCED_FACE('F936',(#1369),#1358,.F.);
#1371=CARTESIAN_POINT('',(0.,6.35,0.));
#1372=DIRECTION('',(0.,-1.,0.));
#1373=DIRECTION('',(0.,0.,-1.));
#1374=AXIS2_PLACEMENT_3D('',#1371,#1372,#1373);
#1375=CYLINDRICAL_SURFACE('',#1374,12.0700000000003);
#1376=ORIENTED_EDGE('',*,*,#761,.F.);
#1377=ORIENTED_EDGE('',*,*,#1366,.F.);
#1378=ORIENTED_EDGE('',*,*,#212,.T.);
#1379=DIRECTION('',(0.,-1.,0.));
#1380=VECTOR('',#1379,1.);
#1381=CARTESIAN_POINT('',(8.79049896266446,6.35,8.2711563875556));
#1382=LINE('',#1381,#1380);
#1383=EDGE_CURVE('E742',#202,#760,#1382,.T.);
#1384=ORIENTED_EDGE('',*,*,#1383,.T.);
#1385=EDGE_LOOP('',(#1376,#1377,#1378,#1384));
#1386=FACE_BOUND('',#1385,.T.);
#1387=ADVANCED_FACE('F940',(#1386),#1375,.T.);
#1388=CARTESIAN_POINT('',(10.2470853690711,6.35,9.6416876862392));
#1389=DIRECTION('',(0.,-1.,0.));
#1390=DIRECTION('',(0.,0.,-1.));
#1391=AXIS2_PLACEMENT_3D('',#1388,#1389,#1390);
#1392=CYLINDRICAL_SURFACE('',#1391,2.);
#1393=ORIENTED_EDGE('',*,*,#770,.F.);
#1394=ORIENTED_EDGE('',*,*,#1383,.F.);
#1395=ORIENTED_EDGE('',*,*,#203,.T.);
#1396=DIRECTION('',(0.,-1.,0.));
#1397=VECTOR('',#1396,1.);
#1398=CARTESIAN_POINT('',(8.68342240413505,6.35,10.8886672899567));
#1399=LINE('',#1398,#1397);
#1400=EDGE_CURVE('E740',#193,#769,#1399,.T.);
#1401=ORIENTED_EDGE('',*,*,#1400,.T.);
#1402=EDGE_LOOP('',(#1393,#1394,#1395,#1401));
#1403=FACE_BOUND('',#1402,.T.);
#1404=ADVANCED_FACE('F944',(#1403),#1392,.F.);
#1405=CARTESIAN_POINT('',(8.68342240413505,6.35,10.8886672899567));
#1406=DIRECTION('',(0.78183148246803,0.,-0.623489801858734));
#1407=DIRECTION('',(-0.623489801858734,0.,-0.78183148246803));
#1408=AXIS2_PLACEMENT_3D('',#1405,#1406,#1407);
#1409=PLANE('',#1408);
#1410=ORIENTED_EDGE('',*,*,#776,.F.);
#1411=ORIENTED_EDGE('',*,*,#1400,.F.);
#1412=ORIENTED_EDGE('',*,*,#194,.T.);
#1413=ORIENTED_EDGE('',*,*,#1291,.T.);
#1414=EDGE_LOOP('',(#1410,#1411,#1412,#1413));
#1415=FACE_BOUND('',#1414,.T.);
#1416=ADVANCED_FACE('F948',(#1415),#1409,.T.);
#1417=CARTESIAN_POINT('',(-3.9720856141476,6.35,39.8726401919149));
#1418=DIRECTION('',(0.,-1.,0.));
#1419=DIRECTION('',(0.,0.,-1.));
#1420=AXIS2_PLACEMENT_3D('',#1417,#1418,#1419);
#1421=CYLINDRICAL_SURFACE('',#1420,5.);
#1422=ORIENTED_EDGE('',*,*,#891,.F.);
#1423=DIRECTION('',(0.,-1.,0.));
#1424=VECTOR('',#1423,1.);
#1425=CARTESIAN_POINT('',(-8.84672517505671,6.35,38.7600355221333));
#1426=LINE('',#1425,#1424);
#1427=EDGE_CURVE('E656',#359,#888,#1426,.T.);
#1428=ORIENTED_EDGE('',*,*,#1427,.F.);
#1429=ORIENTED_EDGE('',*,*,#360,.T.);
#1430=DIRECTION('',(0.,-1.,0.));
#1431=VECTOR('',#1430,1.);
#1432=CARTESIAN_POINT('',(-4.46772894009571,6.35,44.8480133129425));
#1433=LINE('',#1432,#1431);
#1434=EDGE_CURVE('E693',#348,#890,#1433,.T.);
#1435=ORIENTED_EDGE('',*,*,#1434,.T.);
#1436=EDGE_LOOP('',(#1422,#1428,#1429,#1435));
#1437=FACE_BOUND('',#1436,.T.);
#1438=ADVANCED_FACE('F952',(#1437),#1421,.F.);
#1439=CARTESIAN_POINT('',(0.,6.35,0.));
#1440=DIRECTION('',(0.,-1.,0.));
#1441=DIRECTION('',(0.,0.,-1.));
#1442=AXIS2_PLACEMENT_3D('',#1439,#1440,#1441);
#1443=CYLINDRICAL_SURFACE('',#1442,45.0700000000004);
#1444=ORIENTED_EDGE('',*,*,#900,.F.);
#1445=ORIENTED_EDGE('',*,*,#1434,.F.);
#1446=ORIENTED_EDGE('',*,*,#351,.T.);
#1447=DIRECTION('',(0.,-1.,0.));
#1448=VECTOR('',#1447,1.);
#1449=CARTESIAN_POINT('',(7.39021068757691,6.35,44.4599784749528));
#1450=LINE('',#1449,#1448);
#1451=EDGE_CURVE('E691',#350,#899,#1450,.T.);
#1452=ORIENTED_EDGE('',*,*,#1451,.T.);
#1453=EDGE_LOOP('',(#1444,#1445,#1446,#1452));
#1454=FACE_BOUND('',#1453,.T.);
#1455=ADVANCED_FACE('F956',(#1454),#1443,.F.);
#1456=CARTESIAN_POINT('',(6.57035150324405,6.35,39.5276533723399));
#1457=DIRECTION('',(0.,-1.,0.));
#1458=DIRECTION('',(0.,0.,-1.));
#1459=AXIS2_PLACEMENT_3D('',#1456,#1457,#1458);
#1460=CYLINDRICAL_SURFACE('',#1459,5.);
#1461=ORIENTED_EDGE('',*,*,#909,.F.);
#1462=ORIENTED_EDGE('',*,*,#1451,.F.);
#1463=ORIENTED_EDGE('',*,*,#410,.T.);
#1464=DIRECTION('',(0.,-1.,0.));
#1465=VECTOR('',#1464,1.);
#1466=CARTESIAN_POINT('',(11.368993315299,6.35,38.1230051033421));
#1467=LINE('',#1466,#1465);
#1468=EDGE_CURVE('E689',#402,#908,#1467,.T.);
#1469=ORIENTED_EDGE('',*,*,#1468,.T.);
#1470=EDGE_LOOP('',(#1461,#1462,#1463,#1469));
#1471=FACE_BOUND('',#1470,.T.);
#1472=ADVANCED_FACE('F960',(#1471),#1460,.F.);
#1473=CARTESIAN_POINT('',(4.11340421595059,6.35,13.3360360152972));
#1474=DIRECTION('',(-0.959728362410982,0.,0.280929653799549));
#1475=DIRECTION('',(0.280929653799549,0.,0.959728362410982));
#1476=AXIS2_PLACEMENT_3D('',#1473,#1474,#1475);
#1477=PLANE('',#1476);
#1478=ORIENTED_EDGE('',*,*,#917,.F.);
#1479=ORIENTED_EDGE('',*,*,#1468,.F.);
#1480=ORIENTED_EDGE('',*,*,#403,.T.);
#1481=DIRECTION('',(0.,-1.,0.));
#1482=VECTOR('',#1481,1.);
#1483=CARTESIAN_POINT('',(4.1134042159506,6.35,13.3360360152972));
#1484=LINE('',#1483,#1482);
#1485=EDGE_CURVE('E687',#394,#916,#1484,.T.);
#1486=ORIENTED_EDGE('',*,*,#1485,.T.);
#1487=EDGE_LOOP('',(#1478,#1479,#1480,#1486));
#1488=FACE_BOUND('',#1487,.T.);
#1489=ADVANCED_FACE('F964',(#1488),#1477,.T.);
#1490=CARTESIAN_POINT('',(2.19394749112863,6.35,13.8978953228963));
#1491=DIRECTION('',(0.,-1.,0.));
#1492=DIRECTION('',(0.,0.,-1.));
#1493=AXIS2_PLACEMENT_3D('',#1490,#1491,#1492);
#1494=CYLINDRICAL_SURFACE('',#1493,2.);
#1495=ORIENTED_EDGE('',*,*,#926,.F.);
#1496=ORIENTED_EDGE('',*,*,#1485,.F.);
#1497=ORIENTED_EDGE('',*,*,#395,.T.);
#1498=DIRECTION('',(0.,-1.,0.));
#1499=VECTOR('',#1498,1.);
#1500=CARTESIAN_POINT('',(1.88208572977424,6.35,11.922359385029));
#1501=LINE('',#1500,#1499);
#1502=EDGE_CURVE('E685',#385,#925,#1501,.T.);
#1503=ORIENTED_EDGE('',*,*,#1502,.T.);
#1504=EDGE_LOOP('',(#1495,#1496,#1497,#1503));
#1505=FACE_BOUND('',#1504,.T.);
#1506=ADVANCED_FACE('F968',(#1505),#1494,.F.);
#1507=CARTESIAN_POINT('',(0.,6.35,0.));
#1508=DIRECTION('',(0.,-1.,0.));
#1509=DIRECTION('',(0.,0.,-1.));
#1510=AXIS2_PLACEMENT_3D('',#1507,#1508,#1509);
#1511=CYLINDRICAL_SURFACE('',#1510,12.0700000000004);
#1512=ORIENTED_EDGE('',*,*,#935,.F.);
#1513=ORIENTED_EDGE('',*,*,#1502,.F.);
#1514=ORIENTED_EDGE('',*,*,#386,.T.);
#1515=DIRECTION('',(0.,-1.,0.));
#1516=VECTOR('',#1515,1.);
#1517=CARTESIAN_POINT('',(-0.98586400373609,6.35,12.0296704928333));
#1518=LINE('',#1517,#1516);
#1519=EDGE_CURVE('E683',#376,#934,#1518,.T.);
#1520=ORIENTED_EDGE('',*,*,#1519,.T.);
#1521=EDGE_LOOP('',(#1512,#1513,#1514,#1520));
#1522=FACE_BOUND('',#1521,.T.);
#1523=ADVANCED_FACE('F972',(#1522),#1511,.T.);
#1524=CARTESIAN_POINT('',(-1.14922175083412,6.35,14.0229878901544));
#1525=DIRECTION('',(0.,-1.,0.));
#1526=DIRECTION('',(0.,0.,-1.));
#1527=AXIS2_PLACEMENT_3D('',#1524,#1525,#1526);
#1528=CYLINDRICAL_SURFACE('',#1527,2.);
#1529=ORIENTED_EDGE('',*,*,#944,.F.);
#1530=ORIENTED_EDGE('',*,*,#1519,.F.);
#1531=ORIENTED_EDGE('',*,*,#377,.T.);
#1532=DIRECTION('',(0.,-1.,0.));
#1533=VECTOR('',#1532,1.);
#1534=CARTESIAN_POINT('',(-3.09907757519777,6.35,13.5779460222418));
#1535=LINE('',#1534,#1533);
#1536=EDGE_CURVE('E681',#367,#943,#1535,.T.);
#1537=ORIENTED_EDGE('',*,*,#1536,.T.);
#1538=EDGE_LOOP('',(#1529,#1530,#1531,#1537));
#1539=FACE_BOUND('',#1538,.T.);
#1540=ADVANCED_FACE('F976',(#1539),#1528,.F.);
#1541=CARTESIAN_POINT('',(-3.09907757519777,6.35,13.5779460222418));
#1542=DIRECTION('',(0.974927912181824,0.,0.222520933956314));
#1543=DIRECTION('',(0.222520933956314,0.,-0.974927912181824));
#1544=AXIS2_PLACEMENT_3D('',#1541,#1542,#1543);
#1545=PLANE('',#1544);
#1546=ORIENTED_EDGE('',*,*,#950,.F.);
#1547=ORIENTED_EDGE('',*,*,#1536,.F.);
#1548=ORIENTED_EDGE('',*,*,#368,.T.);
#1549=ORIENTED_EDGE('',*,*,#1427,.T.);
#1550=EDGE_LOOP('',(#1546,#1547,#1548,#1549));
#1551=FACE_BOUND('',#1550,.T.);
#1552=ADVANCED_FACE('F980',(#1551),#1545,.T.);
#1553=CARTESIAN_POINT('',(-33.6502402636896,6.35,21.7546829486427));
#1554=DIRECTION('',(0.,-1.,0.));
#1555=DIRECTION('',(0.,0.,-1.));
#1556=AXIS2_PLACEMENT_3D('',#1553,#1554,#1555);
#1557=CYLINDRICAL_SURFACE('',#1556,5.);
#1558=ORIENTED_EDGE('',*,*,#645,.F.);
#1559=DIRECTION('',(0.,-1.,0.));
#1560=VECTOR('',#1559,1.);
#1561=CARTESIAN_POINT('',(-35.8196589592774,6.35,17.2498386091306));
#1562=LINE('',#1561,#1560);
#1563=EDGE_CURVE('E597',#113,#642,#1562,.T.);
#1564=ORIENTED_EDGE('',*,*,#1563,.F.);
#1565=ORIENTED_EDGE('',*,*,#114,.T.);
#1566=DIRECTION('',(0.,-1.,0.));
#1567=VECTOR('',#1566,1.);
#1568=CARTESIAN_POINT('',(-37.8491721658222,6.35,24.469267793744));
#1569=LINE('',#1568,#1567);
#1570=EDGE_CURVE('E634',#102,#644,#1569,.T.);
#1571=ORIENTED_EDGE('',*,*,#1570,.T.);
#1572=EDGE_LOOP('',(#1558,#1564,#1565,#1571));
#1573=FACE_BOUND('',#1572,.T.);
#1574=ADVANCED_FACE('F984',(#1573),#1557,.F.);
#1575=CARTESIAN_POINT('',(0.,6.35,0.));
#1576=DIRECTION('',(0.,-1.,0.));
#1577=DIRECTION('',(0.,0.,-1.));
#1578=AXIS2_PLACEMENT_3D('',#1575,#1576,#1577);
#1579=CYLINDRICAL_SURFACE('',#1578,45.0700000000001);
#1580=ORIENTED_EDGE('',*,*,#654,.F.);
#1581=ORIENTED_EDGE('',*,*,#1570,.F.);
#1582=ORIENTED_EDGE('',*,*,#105,.T.);
#1583=DIRECTION('',(0.,-1.,0.));
#1584=VECTOR('',#1583,1.);
#1585=CARTESIAN_POINT('',(-30.152489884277,6.35,33.4982425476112));
#1586=LINE('',#1585,#1584);
#1587=EDGE_CURVE('E632',#104,#653,#1586,.T.);
#1588=ORIENTED_EDGE('',*,*,#1587,.T.);
#1589=EDGE_LOOP('',(#1580,#1581,#1582,#1588));
#1590=FACE_BOUND('',#1589,.T.);
#1591=ADVANCED_FACE('F988',(#1590),#1579,.F.);
#1592=CARTESIAN_POINT('',(-26.8074166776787,6.35,29.7819964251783));
#1593=DIRECTION('',(0.,-1.,0.));
#1594=DIRECTION('',(0.,0.,-1.));
#1595=AXIS2_PLACEMENT_3D('',#1592,#1593,#1594);
#1596=CYLINDRICAL_SURFACE('',#1595,5.);
#1597=ORIENTED_EDGE('',*,*,#663,.F.);
#1598=ORIENTED_EDGE('',*,*,#1587,.F.);
#1599=ORIENTED_EDGE('',*,*,#164,.T.);
#1600=DIRECTION('',(0.,-1.,0.));
#1601=VECTOR('',#1600,1.);
#1602=CARTESIAN_POINT('',(-22.7173142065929,6.35,32.6579417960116));
#1603=LINE('',#1602,#1601);
#1604=EDGE_CURVE('E630',#156,#662,#1603,.T.);
#1605=ORIENTED_EDGE('',*,*,#1604,.T.);
#1606=EDGE_LOOP('',(#1597,#1598,#1599,#1605));
#1607=FACE_BOUND('',#1606,.T.);
#1608=ADVANCED_FACE('F992',(#1607),#1596,.F.);
#1609=CARTESIAN_POINT('',(-7.86186722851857,6.35,11.5308713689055));
#1610=DIRECTION('',(-0.818020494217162,0.,-0.57518907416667));
#1611=DIRECTION('',(-0.57518907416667,0.,0.818020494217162));
#1612=AXIS2_PLACEMENT_3D('',#1609,#1610,#1611);
#1613=PLANE('',#1612);
#1614=ORIENTED_EDGE('',*,*,#671,.F.);
#1615=ORIENTED_EDGE('',*,*,#1604,.F.);
#1616=ORIENTED_EDGE('',*,*,#157,.T.);
#1617=DIRECTION('',(0.,-1.,0.));
#1618=VECTOR('',#1617,1.);
#1619=CARTESIAN_POINT('',(-7.86186722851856,6.35,11.5308713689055));
#1620=LINE('',#1619,#1618);
#1621=EDGE_CURVE('E628',#148,#670,#1620,.T.);
#1622=ORIENTED_EDGE('',*,*,#1621,.T.);
#1623=EDGE_LOOP('',(#1614,#1615,#1616,#1622));
#1624=FACE_BOUND('',#1623,.T.);
#1625=ADVANCED_FACE('F996',(#1624),#1613,.T.);
#1626=CARTESIAN_POINT('',(-9.49790821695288,6.35,10.3804932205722));
#1627=DIRECTION('',(0.,-1.,0.));
#1628=DIRECTION('',(0.,0.,-1.));
#1629=AXIS2_PLACEMENT_3D('',#1626,#1627,#1628);
#1630=CYLINDRICAL_SURFACE('',#1629,2.);
#1631=ORIENTED_EDGE('',*,*,#680,.F.);
#1632=ORIENTED_EDGE('',*,*,#1621,.F.);
#1633=ORIENTED_EDGE('',*,*,#149,.T.);
#1634=DIRECTION('',(0.,-1.,0.));
#1635=VECTOR('',#1634,1.);
#1636=CARTESIAN_POINT('',(-8.14781465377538,6.35,8.90494336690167));
#1637=LINE('',#1636,#1635);
#1638=EDGE_CURVE('E626',#139,#679,#1637,.T.);
#1639=ORIENTED_EDGE('',*,*,#1638,.T.);
#1640=EDGE_LOOP('',(#1631,#1632,#1633,#1639));
#1641=FACE_BOUND('',#1640,.T.);
#1642=ADVANCED_FACE('F1000',(#1641),#1630,.F.);
#1643=CARTESIAN_POINT('',(0.,6.35,0.));
#1644=DIRECTION('',(0.,-1.,0.));
#1645=DIRECTION('',(0.,0.,-1.));
#1646=AXIS2_PLACEMENT_3D('',#1643,#1644,#1645);
#1647=CYLINDRICAL_SURFACE('',#1646,12.0700000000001);
#1648=ORIENTED_EDGE('',*,*,#689,.F.);
#1649=ORIENTED_EDGE('',*,*,#1638,.F.);
#1650=ORIENTED_EDGE('',*,*,#140,.T.);
#1651=DIRECTION('',(0.,-1.,0.));
#1652=VECTOR('',#1651,1.);
#1653=CARTESIAN_POINT('',(-10.0198512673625,6.35,6.72959735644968));
#1654=LINE('',#1653,#1652);
#1655=EDGE_CURVE('E624',#130,#688,#1654,.T.);
#1656=ORIENTED_EDGE('',*,*,#1655,.T.);
#1657=EDGE_LOOP('',(#1648,#1649,#1650,#1656));
#1658=FACE_BOUND('',#1657,.T.);
#1659=ADVANCED_FACE('F1004',(#1658),#1647,.T.);
#1660=CARTESIAN_POINT('',(-11.6801414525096,6.35,7.84469219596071));
#1661=DIRECTION('',(0.,-1.,0.));
#1662=DIRECTION('',(0.,0.,-1.));
#1663=AXIS2_PLACEMENT_3D('',#1660,#1661,#1662);
#1664=CYLINDRICAL_SURFACE('',#1663,2.);
#1665=ORIENTED_EDGE('',*,*,#698,.F.);
#1666=ORIENTED_EDGE('',*,*,#1655,.F.);
#1667=ORIENTED_EDGE('',*,*,#131,.T.);
#1668=DIRECTION('',(0.,-1.,0.));
#1669=VECTOR('',#1668,1.);
#1670=CARTESIAN_POINT('',(-12.5479089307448,6.35,6.04275446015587));
#1671=LINE('',#1670,#1669);
#1672=EDGE_CURVE('E622',#121,#697,#1671,.T.);
#1673=ORIENTED_EDGE('',*,*,#1672,.T.);
#1674=EDGE_LOOP('',(#1665,#1666,#1667,#1673));
#1675=FACE_BOUND('',#1674,.T.);
#1676=ADVANCED_FACE('F1008',(#1675),#1664,.F.);
#1677=CARTESIAN_POINT('',(-12.5479089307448,6.35,6.04275446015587));
#1678=DIRECTION('',(0.433883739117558,0.,0.900968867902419));
#1679=DIRECTION('',(0.900968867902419,0.,-0.433883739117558));
#1680=AXIS2_PLACEMENT_3D('',#1677,#1678,#1679);
#1681=PLANE('',#1680);
#1682=ORIENTED_EDGE('',*,*,#704,.F.);
#1683=ORIENTED_EDGE('',*,*,#1672,.F.);
#1684=ORIENTED_EDGE('',*,*,#122,.T.);
#1685=ORIENTED_EDGE('',*,*,#1563,.T.);
#1686=EDGE_LOOP('',(#1682,#1683,#1684,#1685));
#1687=FACE_BOUND('',#1686,.T.);
#1688=ADVANCED_FACE('F1012',(#1687),#1681,.T.);
#1689=CARTESIAN_POINT('',(-37.9890776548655,6.35,-12.744994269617));
#1690=DIRECTION('',(0.,-1.,0.));
#1691=DIRECTION('',(0.,0.,-1.));
#1692=AXIS2_PLACEMENT_3D('',#1689,#1690,#1691);
#1693=CYLINDRICAL_SURFACE('',#1692,5.);
#1694=ORIENTED_EDGE('',*,*,#963,.F.);
#1695=DIRECTION('',(0.,-1.,0.));
#1696=VECTOR('',#1695,1.);
#1697=CARTESIAN_POINT('',(-35.8196589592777,6.35,-17.2498386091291));
#1698=LINE('',#1697,#1696);
#1699=EDGE_CURVE('E538',#431,#960,#1698,.T.);
#1700=ORIENTED_EDGE('',*,*,#1699,.F.);
#1701=ORIENTED_EDGE('',*,*,#432,.T.);
#1702=DIRECTION('',(0.,-1.,0.));
#1703=VECTOR('',#1702,1.);
#1704=CARTESIAN_POINT('',(-42.7294167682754,6.35,-14.3353354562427));
#1705=LINE('',#1704,#1703);
#1706=EDGE_CURVE('E575',#420,#962,#1705,.T.);
#1707=ORIENTED_EDGE('',*,*,#1706,.T.);
#1708=EDGE_LOOP('',(#1694,#1700,#1701,#1707));
#1709=FACE_BOUND('',#1708,.T.);
#1710=ADVANCED_FACE('F1016',(#1709),#1693,.F.);
#1711=CARTESIAN_POINT('',(0.,6.35,0.));
#1712=DIRECTION('',(0.,-1.,0.));
#1713=DIRECTION('',(0.,0.,-1.));
#1714=AXIS2_PLACEMENT_3D('',#1711,#1712,#1713);
#1715=CYLINDRICAL_SURFACE('',#1714,45.0699999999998);
#1716=ORIENTED_EDGE('',*,*,#972,.F.);
#1717=ORIENTED_EDGE('',*,*,#1706,.F.);
#1718=ORIENTED_EDGE('',*,*,#423,.T.);
#1719=DIRECTION('',(0.,-1.,0.));
#1720=VECTOR('',#1719,1.);
#1721=CARTESIAN_POINT('',(-44.9897505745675,6.35,-2.68835325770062));
#1722=LINE('',#1721,#1720);
#1723=EDGE_CURVE('E573',#422,#971,#1722,.T.);
#1724=ORIENTED_EDGE('',*,*,#1723,.T.);
#1725=EDGE_LOOP('',(#1716,#1717,#1718,#1724));
#1726=FACE_BOUND('',#1725,.T.);
#1727=ADVANCED_FACE('F1020',(#1726),#1715,.F.);
#1728=CARTESIAN_POINT('',(-39.9986533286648,6.35,-2.39011127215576));
#1729=DIRECTION('',(0.,-1.,0.));
#1730=DIRECTION('',(0.,0.,-1.));
#1731=AXIS2_PLACEMENT_3D('',#1728,#1729,#1730);
#1732=CYLINDRICAL_SURFACE('',#1731,5.);
#1733=ORIENTED_EDGE('',*,*,#981,.F.);
#1734=ORIENTED_EDGE('',*,*,#1723,.F.);
#1735=ORIENTED_EDGE('',*,*,#482,.T.);
#1736=DIRECTION('',(0.,-1.,0.));
#1737=VECTOR('',#1736,1.);
#1738=CARTESIAN_POINT('',(-39.6970207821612,6.35,2.60078221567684));
#1739=LINE('',#1738,#1737);
#1740=EDGE_CURVE('E571',#474,#980,#1739,.T.);
#1741=ORIENTED_EDGE('',*,*,#1740,.T.);
#1742=EDGE_LOOP('',(#1733,#1734,#1735,#1741));
#1743=FACE_BOUND('',#1742,.T.);
#1744=ADVANCED_FACE('F1024',(#1743),#1732,.F.);
#1745=CARTESIAN_POINT('',(-13.9169922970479,6.35,1.04272539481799));
#1746=DIRECTION('',(-0.0603265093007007,0.,-0.998178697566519));
#1747=DIRECTION('',(-0.998178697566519,0.,0.0603265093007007));
#1748=AXIS2_PLACEMENT_3D('',#1745,#1746,#1747);
#1749=PLANE('',#1748);
#1750=ORIENTED_EDGE('',*,*,#989,.F.);
#1751=ORIENTED_EDGE('',*,*,#1740,.F.);
#1752=ORIENTED_EDGE('',*,*,#475,.T.);
#1753=DIRECTION('',(0.,-1.,0.));
#1754=VECTOR('',#1753,1.);
#1755=CARTESIAN_POINT('',(-13.9169922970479,6.35,1.042725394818));
#1756=LINE('',#1755,#1754);
#1757=EDGE_CURVE('E569',#466,#988,#1756,.T.);
#1758=ORIENTED_EDGE('',*,*,#1757,.T.);
#1759=EDGE_LOOP('',(#1750,#1751,#1752,#1758));
#1760=FACE_BOUND('',#1759,.T.);
#1761=ADVANCED_FACE('F1028',(#1760),#1749,.T.);
#1762=CARTESIAN_POINT('',(-14.0376453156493,6.35,-0.953632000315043));
#1763=DIRECTION('',(0.,-1.,0.));
#1764=DIRECTION('',(0.,0.,-1.));
#1765=AXIS2_PLACEMENT_3D('',#1762,#1763,#1764);
#1766=CYLINDRICAL_SURFACE('',#1765,2.);
#1767=ORIENTED_EDGE('',*,*,#998,.F.);
#1768=ORIENTED_EDGE('',*,*,#1757,.F.);
#1769=ORIENTED_EDGE('',*,*,#467,.T.);
#1770=DIRECTION('',(0.,-1.,0.));
#1771=VECTOR('',#1770,1.);
#1772=CARTESIAN_POINT('',(-12.0422444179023,6.35,-0.818076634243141));
#1773=LINE('',#1772,#1771);
#1774=EDGE_CURVE('E567',#457,#997,#1773,.T.);
#1775=ORIENTED_EDGE('',*,*,#1774,.T.);
#1776=EDGE_LOOP('',(#1767,#1768,#1769,#1775));
#1777=FACE_BOUND('',#1776,.T.);
#1778=ADVANCED_FACE('F1032',(#1777),#1766,.F.);
#1779=CARTESIAN_POINT('',(0.,6.35,0.));
#1780=DIRECTION('',(0.,-1.,0.));
#1781=DIRECTION('',(0.,0.,-1.));
#1782=AXIS2_PLACEMENT_3D('',#1779,#1780,#1781);
#1783=CYLINDRICAL_SURFACE('',#1782,12.0699999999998);
#1784=ORIENTED_EDGE('',*,*,#1007,.F.);
#1785=ORIENTED_EDGE('',*,*,#1774,.F.);
#1786=ORIENTED_EDGE('',*,*,#458,.T.);
#1787=DIRECTION('',(0.,-1.,0.));
#1788=VECTOR('',#1787,1.);
#1789=CARTESIAN_POINT('',(-11.5086861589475,6.35,-3.63799984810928));
#1790=LINE('',#1789,#1788);
#1791=EDGE_CURVE('E565',#448,#1006,#1790,.T.);
#1792=ORIENTED_EDGE('',*,*,#1791,.T.);
#1793=EDGE_LOOP('',(#1784,#1785,#1786,#1792));
#1794=FACE_BOUND('',#1793,.T.);
#1795=ADVANCED_FACE('F1036',(#1794),#1783,.T.);
#1796=CARTESIAN_POINT('',(-13.4156764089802,6.35,-4.24081672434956));
#1797=DIRECTION('',(0.,-1.,0.));
#1798=DIRECTION('',(0.,0.,-1.));
#1799=AXIS2_PLACEMENT_3D('',#1796,#1797,#1798);
#1800=CYLINDRICAL_SURFACE('',#1799,2.);
#1801=ORIENTED_EDGE('',*,*,#1016,.F.);
#1802=ORIENTED_EDGE('',*,*,#1791,.F.);
#1803=ORIENTED_EDGE('',*,*,#449,.T.);
#1804=DIRECTION('',(0.,-1.,0.));
#1805=VECTOR('',#1804,1.);
#1806=CARTESIAN_POINT('',(-12.5479089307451,6.35,-6.0427544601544));
#1807=LINE('',#1806,#1805);
#1808=EDGE_CURVE('E563',#439,#1015,#1807,.T.);
#1809=ORIENTED_EDGE('',*,*,#1808,.T.);
#1810=EDGE_LOOP('',(#1801,#1802,#1803,#1809));
#1811=FACE_BOUND('',#1810,.T.);
#1812=ADVANCED_FACE('F1040',(#1811),#1800,.F.);
#1813=CARTESIAN_POINT('',(-12.5479089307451,6.35,-6.0427544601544));
#1814=DIRECTION('',(-0.433883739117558,0.,0.900968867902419));
#1815=DIRECTION('',(0.900968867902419,0.,0.433883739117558));
#1816=AXIS2_PLACEMENT_3D('',#1813,#1814,#1815);
#1817=PLANE('',#1816);
#1818=ORIENTED_EDGE('',*,*,#1022,.F.);
#1819=ORIENTED_EDGE('',*,*,#1808,.F.);
#1820=ORIENTED_EDGE('',*,*,#440,.T.);
#1821=ORIENTED_EDGE('',*,*,#1699,.T.);
#1822=EDGE_LOOP('',(#1818,#1819,#1820,#1821));
#1823=FACE_BOUND('',#1822,.T.);
#1824=ADVANCED_FACE('F1044',(#1823),#1817,.T.);
#1825=CARTESIAN_POINT('',(-13.7213647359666,6.35,-37.6474308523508));
#1826=DIRECTION('',(0.,-1.,0.));
#1827=DIRECTION('',(0.,0.,-1.));
#1828=AXIS2_PLACEMENT_3D('',#1825,#1826,#1827);
#1829=CYLINDRICAL_SURFACE('',#1828,5.);
#1830=ORIENTED_EDGE('',*,*,#573,.F.);
#1831=DIRECTION('',(0.,-1.,0.));
#1832=VECTOR('',#1831,1.);
#1833=CARTESIAN_POINT('',(-8.84672517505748,6.35,-38.7600355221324));
#1834=LINE('',#1833,#1832);
#1835=EDGE_CURVE('E479',#41,#570,#1834,.T.);
#1836=ORIENTED_EDGE('',*,*,#1835,.F.);
#1837=ORIENTED_EDGE('',*,*,#42,.T.);
#1838=DIRECTION('',(0.,-1.,0.));
#1839=VECTOR('',#1838,1.);
#1840=CARTESIAN_POINT('',(-15.4335390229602,6.35,-42.3451387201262));
#1841=LINE('',#1840,#1839);
#1842=EDGE_CURVE('E516',#30,#572,#1841,.T.);
#1843=ORIENTED_EDGE('',*,*,#1842,.T.);
#1844=EDGE_LOOP('',(#1830,#1836,#1837,#1843));
#1845=FACE_BOUND('',#1844,.T.);
#1846=ADVANCED_FACE('F1048',(#1845),#1829,.F.);
#1847=CARTESIAN_POINT('',(0.,6.35,0.));
#1848=DIRECTION('',(0.,-1.,0.));
#1849=DIRECTION('',(0.,0.,-1.));
#1850=AXIS2_PLACEMENT_3D('',#1847,#1848,#1849);
#1851=CYLINDRICAL_SURFACE('',#1850,45.0699999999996);
#1852=ORIENTED_EDGE('',*,*,#582,.F.);
#1853=ORIENTED_EDGE('',*,*,#1842,.F.);
#1854=ORIENTED_EDGE('',*,*,#33,.T.);
#1855=DIRECTION('',(0.,-1.,0.));
#1856=VECTOR('',#1855,1.);
#1857=CARTESIAN_POINT('',(-25.9488114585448,6.35,-36.850564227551));
#1858=LINE('',#1857,#1856);
#1859=EDGE_CURVE('E514',#32,#581,#1858,.T.);
#1860=ORIENTED_EDGE('',*,*,#1859,.T.);
#1861=EDGE_LOOP('',(#1852,#1853,#1854,#1860));
#1862=FACE_BOUND('',#1861,.T.);
#1863=ADVANCED_FACE('F1052',(#1862),#1851,.F.);
#1864=CARTESIAN_POINT('',(-23.0700881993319,6.35,-32.7624164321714));
#1865=DIRECTION('',(0.,-1.,0.));
#1866=DIRECTION('',(0.,0.,-1.));
#1867=AXIS2_PLACEMENT_3D('',#1864,#1865,#1866);
#1868=CYLINDRICAL_SURFACE('',#1867,5.);
#1869=ORIENTED_EDGE('',*,*,#591,.F.);
#1870=ORIENTED_EDGE('',*,*,#1859,.F.);
#1871=ORIENTED_EDGE('',*,*,#92,.T.);
#1872=DIRECTION('',(0.,-1.,0.));
#1873=VECTOR('',#1872,1.);
#1874=CARTESIAN_POINT('',(-26.7840610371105,6.35,-29.4148194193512));
#1875=LINE('',#1874,#1873);
#1876=EDGE_CURVE('E512',#84,#590,#1875,.T.);
#1877=ORIENTED_EDGE('',*,*,#1876,.T.);
#1878=EDGE_LOOP('',(#1869,#1870,#1871,#1877));
#1879=FACE_BOUND('',#1878,.T.);
#1880=ADVANCED_FACE('F1056',(#1879),#1868,.F.);
#1881=CARTESIAN_POINT('',(-9.49233831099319,6.35,-10.2306140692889));
#1882=DIRECTION('',(0.742794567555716,0.,-0.669519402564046));
#1883=DIRECTION('',(-0.669519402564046,0.,-0.742794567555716));
#1884=AXIS2_PLACEMENT_3D('',#1881,#1882,#1883);
#1885=PLANE('',#1884);
#1886=ORIENTED_EDGE('',*,*,#599,.F.);
#1887=ORIENTED_EDGE('',*,*,#1876,.F.);
#1888=ORIENTED_EDGE('',*,*,#85,.T.);
#1889=DIRECTION('',(0.,-1.,0.));
#1890=VECTOR('',#1889,1.);
#1891=CARTESIAN_POINT('',(-9.49233831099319,6.35,-10.2306140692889));
#1892=LINE('',#1891,#1890);
#1893=EDGE_CURVE('E510',#76,#598,#1892,.T.);
#1894=ORIENTED_EDGE('',*,*,#1893,.T.);
#1895=EDGE_LOOP('',(#1886,#1887,#1888,#1894));
#1896=FACE_BOUND('',#1895,.T.);
#1897=ADVANCED_FACE('F1060',(#1896),#1885,.T.);
#1898=CARTESIAN_POINT('',(-8.00674917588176,6.35,-11.569652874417));
#1899=DIRECTION('',(0.,-1.,0.));
#1900=DIRECTION('',(0.,0.,-1.));
#1901=AXIS2_PLACEMENT_3D('',#1898,#1899,#1900);
#1902=CYLINDRICAL_SURFACE('',#1901,2.);
#1903=ORIENTED_EDGE('',*,*,#608,.F.);
#1904=ORIENTED_EDGE('',*,*,#1893,.F.);
#1905=ORIENTED_EDGE('',*,*,#77,.T.);
#1906=DIRECTION('',(0.,-1.,0.));
#1907=VECTOR('',#1906,1.);
#1908=CARTESIAN_POINT('',(-6.86861851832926,6.35,-9.92506824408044));
#1909=LINE('',#1908,#1907);
#1910=EDGE_CURVE('E508',#67,#607,#1909,.T.);
#1911=ORIENTED_EDGE('',*,*,#1910,.T.);
#1912=EDGE_LOOP('',(#1903,#1904,#1905,#1911));
#1913=FACE_BOUND('',#1912,.T.);
#1914=ADVANCED_FACE('F1064',(#1913),#1902,.F.);
#1915=CARTESIAN_POINT('',(0.,6.35,0.));
#1916=DIRECTION('',(0.,-1.,0.));
#1917=DIRECTION('',(0.,0.,-1.));
#1918=AXIS2_PLACEMENT_3D('',#1915,#1916,#1917);
#1919=CYLINDRICAL_SURFACE('',#1918,12.0699999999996);
#1920=ORIENTED_EDGE('',*,*,#617,.F.);
#1921=ORIENTED_EDGE('',*,*,#1910,.F.);
#1922=ORIENTED_EDGE('',*,*,#68,.T.);
#1923=DIRECTION('',(0.,-1.,0.));
#1924=VECTOR('',#1923,1.);
#1925=CARTESIAN_POINT('',(-4.33124563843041,6.35,-11.2661089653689));
#1926=LINE('',#1925,#1924);
#1927=EDGE_CURVE('E506',#58,#616,#1926,.T.);
#1928=ORIENTED_EDGE('',*,*,#1927,.T.);
#1929=EDGE_LOOP('',(#1920,#1921,#1922,#1928));
#1930=FACE_BOUND('',#1929,.T.);
#1931=ADVANCED_FACE('F1068',(#1930),#1919,.T.);
#1932=CARTESIAN_POINT('',(-5.04893339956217,6.35,-13.1329041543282));
#1933=DIRECTION('',(0.,-1.,0.));
#1934=DIRECTION('',(0.,0.,-1.));
#1935=AXIS2_PLACEMENT_3D('',#1932,#1933,#1934);
#1936=CYLINDRICAL_SURFACE('',#1935,2.);
#1937=ORIENTED_EDGE('',*,*,#626,.F.);
#1938=ORIENTED_EDGE('',*,*,#1927,.F.);
#1939=ORIENTED_EDGE('',*,*,#59,.T.);
#1940=DIRECTION('',(0.,-1.,0.));
#1941=VECTOR('',#1940,1.);
#1942=CARTESIAN_POINT('',(-3.09907757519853,6.35,-13.5779460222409));
#1943=LINE('',#1942,#1941);
#1944=EDGE_CURVE('E504',#49,#625,#1943,.T.);
#1945=ORIENTED_EDGE('',*,*,#1944,.T.);
#1946=EDGE_LOOP('',(#1937,#1938,#1939,#1945));
#1947=FACE_BOUND('',#1946,.T.);
#1948=ADVANCED_FACE('F1072',(#1947),#1936,.F.);
#1949=CARTESIAN_POINT('',(-3.09907757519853,6.35,-13.5779460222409));
#1950=DIRECTION('',(-0.974927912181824,0.,0.222520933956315));
#1951=DIRECTION('',(0.222520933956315,0.,0.974927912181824));
#1952=AXIS2_PLACEMENT_3D('',#1949,#1950,#1951);
#1953=PLANE('',#1952);
#1954=ORIENTED_EDGE('',*,*,#632,.F.);
#1955=ORIENTED_EDGE('',*,*,#1944,.F.);
#1956=ORIENTED_EDGE('',*,*,#50,.T.);
#1957=ORIENTED_EDGE('',*,*,#1835,.T.);
#1958=EDGE_LOOP('',(#1954,#1955,#1956,#1957));
#1959=FACE_BOUND('',#1958,.T.);
#1960=ADVANCED_FACE('F1076',(#1959),#1953,.T.);
#1961=CARTESIAN_POINT('',(20.8788156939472,6.35,-34.2005841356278));
#1962=DIRECTION('',(0.,-1.,0.));
#1963=DIRECTION('',(0.,0.,-1.));
#1964=AXIS2_PLACEMENT_3D('',#1961,#1962,#1963);
#1965=CYLINDRICAL_SURFACE('',#1964,5.);
#1966=ORIENTED_EDGE('',*,*,#1035,.F.);
#1967=DIRECTION('',(0.,-1.,0.));
#1968=VECTOR('',#1967,1.);
#1969=CARTESIAN_POINT('',(24.7879731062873,6.35,-31.0831351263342));
#1970=LINE('',#1969,#1968);
#1971=EDGE_CURVE('E400',#503,#1032,#1970,.T.);
#1972=ORIENTED_EDGE('',*,*,#1971,.F.);
#1973=ORIENTED_EDGE('',*,*,#504,.T.);
#1974=DIRECTION('',(0.,-1.,0.));
#1975=VECTOR('',#1974,1.);
#1976=CARTESIAN_POINT('',(23.4841083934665,6.35,-38.4681888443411));
#1977=LINE('',#1976,#1975);
#1978=EDGE_CURVE('E399',#492,#1034,#1977,.T.);
#1979=ORIENTED_EDGE('',*,*,#1978,.T.);
#1980=EDGE_LOOP('',(#1966,#1972,#1973,#1979));
#1981=FACE_BOUND('',#1980,.T.);
#1982=ADVANCED_FACE('F398',(#1981),#1965,.F.);
#1983=CARTESIAN_POINT('',(0.,6.35,0.));
#1984=DIRECTION('',(0.,-1.,0.));
#1985=DIRECTION('',(0.,0.,-1.));
#1986=AXIS2_PLACEMENT_3D('',#1983,#1984,#1985);
#1987=CYLINDRICAL_SURFACE('',#1986,45.0699999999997);
#1988=ORIENTED_EDGE('',*,*,#1044,.F.);
#1989=ORIENTED_EDGE('',*,*,#1978,.F.);
#1990=ORIENTED_EDGE('',*,*,#495,.T.);
#1991=DIRECTION('',(0.,-1.,0.));
#1992=VECTOR('',#1991,1.);
#1993=CARTESIAN_POINT('',(12.6321119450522,6.35,-43.2635487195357));
#1994=LINE('',#1993,#1992);
#1995=EDGE_CURVE('E413',#494,#1043,#1994,.T.);
#1996=ORIENTED_EDGE('',*,*,#1995,.T.);
#1997=EDGE_LOOP('',(#1988,#1989,#1990,#1996));
#1998=FACE_BOUND('',#1997,.T.);
#1999=ADVANCED_FACE('F408',(#1998),#1987,.F.);
#2000=CARTESIAN_POINT('',(11.2307238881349,6.35,-38.4639537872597));
#2001=DIRECTION('',(0.,-1.,0.));
#2002=DIRECTION('',(0.,0.,-1.));
#2003=AXIS2_PLACEMENT_3D('',#2000,#2001,#2002);
#2004=CYLINDRICAL_SURFACE('',#2003,5.);
#2005=ORIENTED_EDGE('',*,*,#1053,.F.);
#2006=ORIENTED_EDGE('',*,*,#1995,.F.);
#2007=ORIENTED_EDGE('',*,*,#554,.T.);
#2008=DIRECTION('',(0.,-1.,0.));
#2009=VECTOR('',#2008,1.);
#2010=CARTESIAN_POINT('',(6.29784296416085,6.35,-39.28046207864));
#2011=LINE('',#2010,#2009);
#2012=EDGE_CURVE('E458',#546,#1052,#2011,.T.);
#2013=ORIENTED_EDGE('',*,*,#2012,.T.);
#2014=EDGE_LOOP('',(#2005,#2006,#2007,#2013));
#2015=FACE_BOUND('',#2014,.T.);
#2016=ADVANCED_FACE('F865',(#2015),#2004,.F.);
#2017=CARTESIAN_POINT('',(2.0802400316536,6.35,-13.800092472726));
#2018=DIRECTION('',(0.986576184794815,0.,0.16330165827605));
#2019=DIRECTION('',(0.16330165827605,0.,-0.986576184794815));
#2020=AXIS2_PLACEMENT_3D('',#2017,#2018,#2019);
#2021=PLANE('',#2020);
#2022=ORIENTED_EDGE('',*,*,#1061,.F.);
#2023=ORIENTED_EDGE('',*,*,#2012,.F.);
#2024=ORIENTED_EDGE('',*,*,#547,.T.);
#2025=DIRECTION('',(0.,-1.,0.));
#2026=VECTOR('',#2025,1.);
#2027=CARTESIAN_POINT('',(2.0802400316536,6.35,-13.800092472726));
#2028=LINE('',#2027,#2026);
#2029=EDGE_CURVE('E456',#538,#1060,#2028,.T.);
#2030=ORIENTED_EDGE('',*,*,#2029,.T.);
#2031=EDGE_LOOP('',(#2022,#2023,#2024,#2030));
#2032=FACE_BOUND('',#2031,.T.);
#2033=ADVANCED_FACE('F862',(#2032),#2021,.T.);
#2034=CARTESIAN_POINT('',(4.05339240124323,6.35,-13.4734891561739));
#2035=DIRECTION('',(0.,-1.,0.));
#2036=DIRECTION('',(0.,0.,-1.));
#2037=AXIS2_PLACEMENT_3D('',#2034,#2035,#2036);
#2038=CYLINDRICAL_SURFACE('',#2037,2.);
#2039=ORIENTED_EDGE('',*,*,#1070,.F.);
#2040=ORIENTED_EDGE('',*,*,#2029,.F.);
#2041=ORIENTED_EDGE('',*,*,#539,.T.);
#2042=DIRECTION('',(0.,-1.,0.));
#2043=VECTOR('',#2042,1.);
#2044=CARTESIAN_POINT('',(3.47721721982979,6.35,-11.5582810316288));
#2045=LINE('',#2044,#2043);
#2046=EDGE_CURVE('E454',#529,#1069,#2045,.T.);
#2047=ORIENTED_EDGE('',*,*,#2046,.T.);
#2048=EDGE_LOOP('',(#2039,#2040,#2041,#2047));
#2049=FACE_BOUND('',#2048,.T.);
#2050=ADVANCED_FACE('F857',(#2049),#2038,.F.);
#2051=CARTESIAN_POINT('',(0.,6.35,0.));
#2052=DIRECTION('',(0.,-1.,0.));
#2053=DIRECTION('',(0.,0.,-1.));
#2054=AXIS2_PLACEMENT_3D('',#2051,#2052,#2053);
#2055=CYLINDRICAL_SURFACE('',#2054,12.0699999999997);
#2056=ORIENTED_EDGE('',*,*,#1079,.F.);
#2057=ORIENTED_EDGE('',*,*,#2046,.F.);
#2058=ORIENTED_EDGE('',*,*,#530,.T.);
#2059=DIRECTION('',(0.,-1.,0.));
#2060=VECTOR('',#2059,1.);
#2061=CARTESIAN_POINT('',(6.10771118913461,6.35,-10.410608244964));
#2062=LINE('',#2061,#2060);
#2063=EDGE_CURVE('E452',#520,#1078,#2062,.T.);
#2064=ORIENTED_EDGE('',*,*,#2063,.T.);
#2065=EDGE_LOOP('',(#2056,#2057,#2058,#2064));
#2066=FACE_BOUND('',#2065,.T.);
#2067=ADVANCED_FACE('F853',(#2066),#2055,.T.);
#2068=CARTESIAN_POINT('',(7.11975943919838,6.35,-12.1356468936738));
#2069=DIRECTION('',(0.,-1.,0.));
#2070=DIRECTION('',(0.,0.,-1.));
#2071=AXIS2_PLACEMENT_3D('',#2068,#2069,#2070);
#2072=CYLINDRICAL_SURFACE('',#2071,2.);
#2073=ORIENTED_EDGE('',*,*,#1088,.F.);
#2074=ORIENTED_EDGE('',*,*,#2063,.F.);
#2075=ORIENTED_EDGE('',*,*,#521,.T.);
#2076=DIRECTION('',(0.,-1.,0.));
#2077=VECTOR('',#2076,1.);
#2078=CARTESIAN_POINT('',(8.68342240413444,6.35,-10.8886672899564));
#2079=LINE('',#2078,#2077);
#2080=EDGE_CURVE('E46',#511,#1087,#2079,.T.);
#2081=ORIENTED_EDGE('',*,*,#2080,.T.);
#2082=EDGE_LOOP('',(#2073,#2074,#2075,#2081));
#2083=FACE_BOUND('',#2082,.T.);
#2084=ADVANCED_FACE('F850',(#2083),#2072,.F.);
#2085=CARTESIAN_POINT('',(8.68342240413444,6.35,-10.8886672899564));
#2086=DIRECTION('',(-0.78183148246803,0.,-0.623489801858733));
#2087=DIRECTION('',(-0.623489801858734,0.,0.78183148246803));
#2088=AXIS2_PLACEMENT_3D('',#2085,#2086,#2087);
#2089=PLANE('',#2088);
#2090=ORIENTED_EDGE('',*,*,#1094,.F.);
#2091=ORIENTED_EDGE('',*,*,#2080,.F.);
#2092=ORIENTED_EDGE('',*,*,#512,.T.);
#2093=ORIENTED_EDGE('',*,*,#1971,.T.);
#2094=EDGE_LOOP('',(#2090,#2091,#2092,#2093));
#2095=FACE_BOUND('',#2094,.T.);
#2096=ADVANCED_FACE('F844',(#2095),#2089,.T.);
#2097=CLOSED_SHELL('',(#558,#1098,#1110,#1132,#1149,#1166,#1183,#1200,#1217,#1234,#1246,#1268,
#1280,#1302,#1319,#1336,#1353,#1370,#1387,#1404,#1416,#1438,#1455,#1472,#1489,#1506,#1523,#1540,
#1552,#1574,#1591,#1608,#1625,#1642,#1659,#1676,#1688,#1710,#1727,#1744,#1761,#1778,#1795,#1812,
#1824,#1846,#1863,#1880,#1897,#1914,#1931,#1948,#1960,#1982,#1999,#2016,#2033,#2050,#2067,#2084,#2096));
#2098=MANIFOLD_SOLID_BREP('B2',#2097);
#2099=ADVANCED_BREP_SHAPE_REPRESENTATION('',(#18,#2098),#14);
#2100=SHAPE_DEFINITION_REPRESENTATION(#9,#2099);
ENDSEC;
END-ISO-10303-21;
